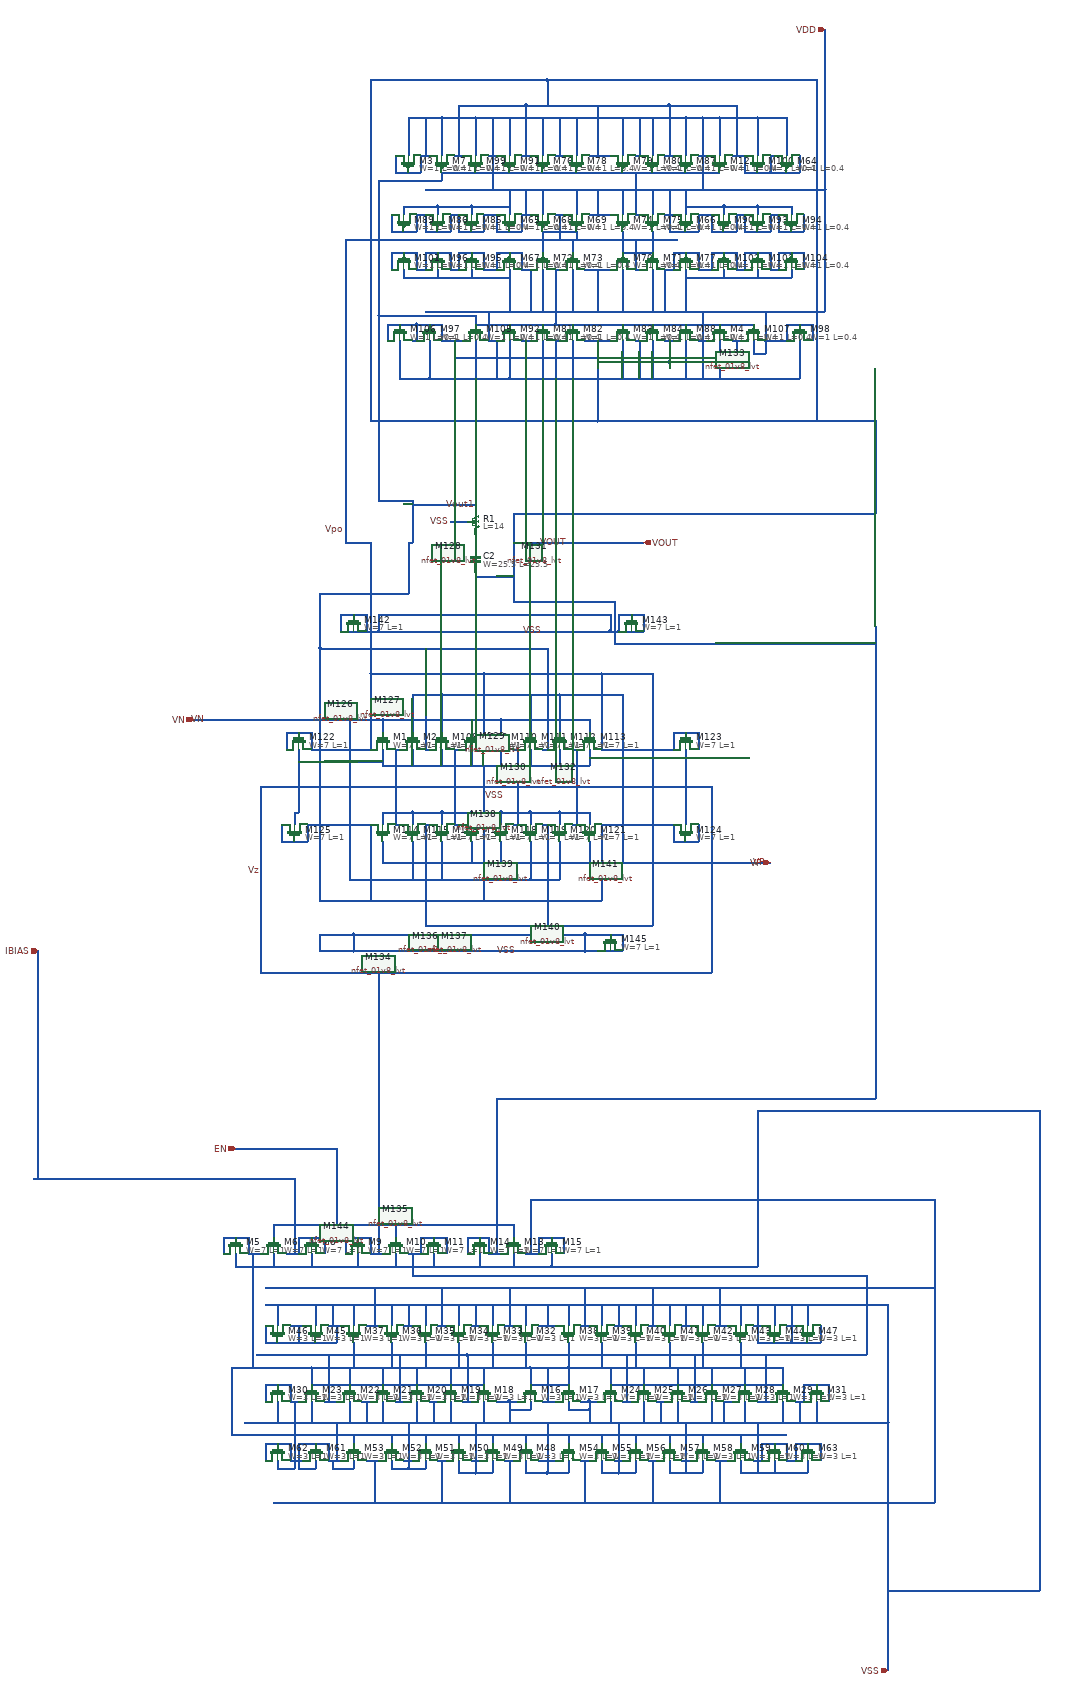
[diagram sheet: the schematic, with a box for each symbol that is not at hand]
v {xschem version=3.4.8RC file_version=1.2}
G {}
K {}
V {}
S {}
F {}
E {}
N 360 -1340 360 -1280 {lab=Vpo}
N 520 -1340 520 -1280 {lab=Vout1}
N 0 -860 40 -860 {lab=VN}
N 360 -1380 360 -1340 {lab=Vpo}
N 520 -1380 520 -1340 {lab=Vout1}
N -370 -310 -370 -70 {lab=IBIAS}
N 760 -1320 760 -1240 {lab=VOUT}
N 520 -1370 670 -1370 {lab=Vout1}
N 990 -1280 1070 -1280 {lab=VOUT}
N 890 -1280 990 -1280 {lab=VOUT}
N 760 -1280 890 -1280 {lab=VOUT}
N -370 -70 -370 -30 {lab=IBIAS}
N 760 -1340 760 -1320 {lab=VOUT}
N 760 -1240 760 -1190 {lab=VOUT}
N 670 -1290 670 -1270 {lab=#net1}
N 670 -1210 670 -1200 {lab=VOUT}
N 670 -1200 760 -1200 {lab=VOUT}
N 670 -1370 670 -1360 {lab=Vout1}
N 670 -1300 670 -1290 {lab=#net1}
N 1340 -520 1360 -520 {lab=VP}
N 1360 -520 1370 -520 {lab=VP}
N 610 -1330 650 -1330 {lab=VSS}
N 70 370 70 410 {lab=#net2}
N 70 370 100 370 {lab=#net2}
N 100 370 130 370 {lab=#net2}
N 130 370 130 410 {lab=#net2}
N 130 410 160 410 {lab=#net2}
N 220 410 250 410 {lab=IBIAS}
N 250 370 250 410 {lab=IBIAS}
N 250 370 280 370 {lab=IBIAS}
N 280 370 310 370 {lab=IBIAS}
N 310 370 310 410 {lab=IBIAS}
N 360 370 360 410 {lab=Vz}
N 360 370 390 370 {lab=Vz}
N 390 370 420 370 {lab=Vz}
N 420 370 420 410 {lab=Vz}
N 420 410 450 410 {lab=Vz}
N 510 410 540 410 {lab=#net3}
N 540 370 540 410 {lab=#net3}
N 540 370 570 370 {lab=#net3}
N 570 370 600 370 {lab=#net3}
N 600 370 600 410 {lab=#net3}
N 670 370 700 370 {lab=VOUT}
N 700 370 700 410 {lab=VOUT}
N 700 410 730 410 {lab=VOUT}
N 790 410 820 410 {lab=#net4}
N 820 370 820 410 {lab=#net4}
N 820 370 850 370 {lab=#net4}
N 850 370 880 370 {lab=#net4}
N 880 370 880 410 {lab=#net4}
N 190 340 570 340 {lab=EN}
N 570 340 760 340 {lab=EN}
N 760 340 760 370 {lab=EN}
N 480 340 480 370 {lab=EN}
N 830 760 860 760 {lab=#net2}
N 100 160 190 160 {lab=EN}
N 800 680 880 680 {lab=#net2}
N 890 680 890 720 {lab=#net2}
N 880 680 890 680 {lab=#net2}
N 800 680 800 720 {lab=#net2}
N 840 680 840 760 {lab=#net2}
N 800 720 840 720 {lab=#net2}
N 840 720 890 720 {lab=#net2}
N 750 760 770 760 {lab=VSS}
N 920 760 940 760 {lab=VSS}
N 720 760 750 760 {lab=VSS}
N 640 760 660 760 {lab=#net3}
N 560 760 580 760 {lab=VSS}
N 480 760 500 760 {lab=#net3}
N 400 760 420 760 {lab=VSS}
N 310 760 340 760 {lab=#net3}
N 280 680 800 680 {lab=#net2}
N 690 680 690 720 {lab=#net2}
N 610 680 610 720 {lab=#net2}
N 530 680 530 720 {lab=#net2}
N 450 680 450 720 {lab=#net2}
N 370 680 370 720 {lab=#net2}
N 280 680 280 720 {lab=#net2}
N 280 720 690 720 {lab=#net2}
N 650 650 650 760 {lab=#net3}
N 590 650 650 650 {lab=#net3}
N 940 760 960 760 {lab=VSS}
N 1020 760 1040 760 {lab=#net3}
N 1100 760 1120 760 {lab=VSS}
N 1180 760 1200 760 {lab=#net3}
N 1260 760 1280 760 {lab=VSS}
N 1340 760 1370 760 {lab=#net3}
N 650 650 1420 650 {lab=#net3}
N 150 650 590 650 {lab=#net3}
N 1030 650 1030 760 {lab=#net3}
N 800 280 800 410 {lab=#net4}
N 800 280 1170 280 {lab=#net4}
N 320 650 320 760 {lab=#net3}
N 1360 650 1360 760 {lab=#net3}
N 890 680 1400 680 {lab=#net2}
N 1400 680 1400 720 {lab=#net2}
N 1310 680 1310 720 {lab=#net2}
N 1230 680 1230 720 {lab=#net2}
N 1150 680 1150 720 {lab=#net2}
N 1070 680 1070 720 {lab=#net2}
N 990 690 990 720 {lab=#net2}
N 990 680 990 690 {lab=#net2}
N 990 720 1400 720 {lab=#net2}
N 490 650 490 760 {lab=#net3}
N 1190 650 1190 760 {lab=#net3}
N 230 760 250 760 {lab=VSS}
N 230 720 230 760 {lab=VSS}
N 200 720 230 720 {lab=VSS}
N 170 720 200 720 {lab=VSS}
N 170 720 170 760 {lab=VSS}
N 1430 760 1450 760 {lab=VSS}
N 1450 720 1450 760 {lab=VSS}
N 1450 720 1480 720 {lab=VSS}
N 1480 720 1510 720 {lab=VSS}
N 1510 720 1510 760 {lab=VSS}
N 90 680 280 680 {lab=#net2}
N 90 680 90 840 {lab=#net2}
N 90 840 1410 840 {lab=#net2}
N 190 340 190 370 {lab=EN}
N 440 60 440 410 {lab=Vz}
N 720 40 720 410 {lab=VOUT}
N 340 160 340 340 {lab=EN}
N 190 160 340 160 {lab=EN}
N -380 230 240 230 {lab=IBIAS}
N 240 230 240 410 {lab=IBIAS}
N 140 410 140 680 {lab=#net2}
N 380 620 380 680 {lab=#net2}
N 470 620 470 680 {lab=#net2}
N 550 620 550 680 {lab=#net2}
N 630 620 630 680 {lab=#net2}
N 710 620 710 680 {lab=#net2}
N 790 620 790 680 {lab=#net2}
N 890 620 890 680 {lab=#net2}
N 970 620 970 680 {lab=#net2}
N 1050 620 1050 680 {lab=#net2}
N 1130 620 1130 680 {lab=#net2}
N 1210 620 1210 680 {lab=#net2}
N 1300 620 1300 680 {lab=#net2}
N 380 840 380 860 {lab=#net2}
N 470 840 470 860 {lab=#net2}
N 550 840 550 860 {lab=#net2}
N 630 840 630 860 {lab=#net2}
N 710 840 710 860 {lab=#net2}
N 790 840 790 860 {lab=#net2}
N 890 840 890 860 {lab=#net2}
N 970 840 970 860 {lab=#net2}
N 1050 840 1050 860 {lab=#net2}
N 1130 840 1130 860 {lab=#net2}
N 1210 840 1210 860 {lab=#net2}
N 1300 840 1300 860 {lab=#net2}
N 230 580 260 580 {lab=VSS}
N 320 580 350 580 {lab=VSS}
N 410 580 440 580 {lab=#net4}
N 500 580 520 580 {lab=VSS}
N 580 580 600 580 {lab=#net4}
N 660 580 680 580 {lab=VSS}
N 740 580 760 580 {lab=#net4}
N 820 580 860 580 {lab=VSS}
N 920 580 940 580 {lab=#net4}
N 1000 580 1020 580 {lab=VSS}
N 1080 580 1100 580 {lab=#net4}
N 1160 580 1180 580 {lab=VSS}
N 1240 580 1270 580 {lab=#net4}
N 1330 580 1350 580 {lab=VSS}
N 1410 580 1430 580 {lab=VSS}
N 1340 580 1340 620 {lab=VSS}
N 1340 620 1380 620 {lab=VSS}
N 1380 620 1420 620 {lab=VSS}
N 1420 580 1420 620 {lab=VSS}
N 1420 620 1460 620 {lab=VSS}
N 1460 620 1490 620 {lab=VSS}
N 1490 580 1490 620 {lab=VSS}
N 1410 900 1430 900 {lab=VSS}
N 1430 860 1430 900 {lab=VSS}
N 1430 860 1460 860 {lab=VSS}
N 1460 860 1490 860 {lab=VSS}
N 1490 860 1490 900 {lab=VSS}
N 1410 860 1410 900 {lab=VSS}
N 1380 860 1410 860 {lab=VSS}
N 1350 860 1380 860 {lab=VSS}
N 1350 860 1350 900 {lab=VSS}
N 1330 900 1350 900 {lab=VSS}
N 1240 900 1270 900 {lab=#net4}
N 1160 900 1180 900 {lab=VSS}
N 1080 900 1100 900 {lab=#net4}
N 1000 900 1020 900 {lab=VSS}
N 920 900 940 900 {lab=#net4}
N 820 900 860 900 {lab=VSS}
N 740 900 760 900 {lab=#net4}
N 660 900 680 900 {lab=VSS}
N 580 900 600 900 {lab=#net4}
N 500 900 520 900 {lab=VSS}
N 410 900 440 900 {lab=#net4}
N 320 900 350 900 {lab=VSS}
N 230 900 260 900 {lab=VSS}
N 320 860 320 900 {lab=VSS}
N 290 860 320 860 {lab=VSS}
N 250 860 290 860 {lab=VSS}
N 250 860 250 900 {lab=VSS}
N 230 860 230 900 {lab=VSS}
N 200 860 230 860 {lab=VSS}
N 170 860 200 860 {lab=VSS}
N 170 860 170 900 {lab=VSS}
N 120 810 1650 810 {lab=VSS}
N 240 760 240 810 {lab=VSS}
N 240 810 240 900 {lab=VSS}
N 200 760 200 810 {lab=VSS}
N 280 760 280 810 {lab=VSS}
N 370 760 370 810 {lab=VSS}
N 410 760 410 810 {lab=VSS}
N 450 760 450 810 {lab=VSS}
N 170 580 170 620 {lab=VSS}
N 170 620 200 620 {lab=VSS}
N 200 620 250 620 {lab=VSS}
N 250 580 250 620 {lab=VSS}
N 240 620 290 620 {lab=VSS}
N 290 620 340 620 {lab=VSS}
N 340 580 340 620 {lab=VSS}
N 200 900 200 920 {lab=VSS}
N 200 920 240 920 {lab=VSS}
N 240 900 240 920 {lab=VSS}
N 290 900 290 920 {lab=VSS}
N 250 920 290 920 {lab=VSS}
N 250 900 250 920 {lab=VSS}
N 380 900 380 920 {lab=VSS}
N 330 920 380 920 {lab=VSS}
N 330 900 330 920 {lab=VSS}
N 340 810 340 900 {lab=VSS}
N 470 900 470 920 {lab=VSS}
N 470 920 510 920 {lab=VSS}
N 510 900 510 920 {lab=VSS}
N 510 810 510 900 {lab=VSS}
N 570 760 570 810 {lab=VSS}
N 530 760 530 810 {lab=VSS}
N 550 900 550 920 {lab=VSS}
N 510 920 550 920 {lab=VSS}
N 670 810 670 900 {lab=VSS}
N 610 760 610 810 {lab=VSS}
N 670 900 670 930 {lab=VSS}
N 630 930 670 930 {lab=VSS}
N 630 900 630 930 {lab=VSS}
N 670 930 710 930 {lab=VSS}
N 710 900 710 930 {lab=VSS}
N 690 760 690 810 {lab=VSS}
N 750 760 750 810 {lab=VSS}
N 800 760 800 780 {lab=VSS}
N 750 780 800 780 {lab=VSS}
N 840 810 840 900 {lab=VSS}
N 790 900 790 930 {lab=VSS}
N 790 930 840 930 {lab=VSS}
N 840 900 840 930 {lab=VSS}
N 840 930 890 930 {lab=VSS}
N 890 900 890 930 {lab=VSS}
N 890 760 890 780 {lab=VSS}
N 890 780 940 780 {lab=VSS}
N 940 760 940 780 {lab=VSS}
N 940 780 940 810 {lab=VSS}
N 1010 810 1010 900 {lab=VSS}
N 970 900 970 930 {lab=VSS}
N 970 930 1010 930 {lab=VSS}
N 1010 900 1010 930 {lab=VSS}
N 1050 900 1050 930 {lab=VSS}
N 1010 930 1050 930 {lab=VSS}
N 990 760 990 810 {lab=VSS}
N 1110 760 1110 810 {lab=VSS}
N 1070 760 1070 810 {lab=VSS}
N 1170 810 1170 900 {lab=VSS}
N 1130 900 1130 930 {lab=VSS}
N 1130 930 1210 930 {lab=VSS}
N 1210 900 1210 930 {lab=VSS}
N 1170 900 1170 930 {lab=VSS}
N 1150 760 1150 810 {lab=VSS}
N 1230 760 1230 810 {lab=VSS}
N 1310 760 1310 810 {lab=VSS}
N 1400 760 1400 810 {lab=VSS}
N 1440 760 1440 810 {lab=VSS}
N 1260 760 1260 810 {lab=VSS}
N 1340 810 1340 900 {lab=VSS}
N 1300 900 1300 930 {lab=VSS}
N 1300 930 1460 930 {lab=VSS}
N 1460 900 1460 930 {lab=VSS}
N 1380 900 1380 930 {lab=VSS}
N 170 530 1580 530 {lab=VSS}
N 1650 530 1650 810 {lab=VSS}
N 1580 530 1650 530 {lab=VSS}
N 1650 810 1650 1340 {lab=VSS}
N 200 530 200 580 {lab=VSS}
N 330 530 330 580 {lab=VSS}
N 290 530 290 580 {lab=VSS}
N 380 530 380 580 {lab=VSS}
N 510 530 510 580 {lab=VSS}
N 470 530 470 580 {lab=VSS}
N 550 530 550 580 {lab=VSS}
N 630 530 630 580 {lab=VSS}
N 670 530 670 580 {lab=VSS}
N 710 530 710 580 {lab=VSS}
N 790 530 790 580 {lab=VSS}
N 840 530 840 580 {lab=VSS}
N 890 530 890 580 {lab=VSS}
N 970 530 970 580 {lab=VSS}
N 1010 530 1010 580 {lab=VSS}
N 1050 530 1050 580 {lab=VSS}
N 1130 530 1130 580 {lab=VSS}
N 1170 530 1170 580 {lab=VSS}
N 1210 530 1210 580 {lab=VSS}
N 1300 530 1300 580 {lab=VSS}
N 1340 530 1340 580 {lab=VSS}
N 1380 530 1380 580 {lab=VSS}
N 1420 530 1420 580 {lab=VSS}
N 1460 530 1460 580 {lab=VSS}
N 1420 650 1580 650 {lab=#net3}
N 520 460 1580 460 {lab=#net3}
N 520 410 520 460 {lab=#net3}
N 190 1000 1760 1000 {lab=#net4}
N 1760 280 1760 1000 {lab=#net4}
N 1170 280 1760 280 {lab=#net4}
N 170 490 1760 490 {lab=#net4}
N 430 490 430 580 {lab=#net4}
N 590 490 590 580 {lab=#net4}
N 750 490 750 580 {lab=#net4}
N 930 490 930 580 {lab=#net4}
N 1090 490 1090 580 {lab=#net4}
N 1250 490 1250 580 {lab=#net4}
N 430 900 430 1000 {lab=#net4}
N 590 900 590 1000 {lab=#net4}
N 750 900 750 1000 {lab=#net4}
N 930 900 930 1000 {lab=#net4}
N 1090 900 1090 1000 {lab=#net4}
N 1250 900 1250 1000 {lab=#net4}
N 760 -1190 760 -1160 {lab=VOUT}
N 720 40 760 40 {lab=VOUT}
N -370 -30 -370 230 {lab=IBIAS}
N 2010 70 2010 1210 {lab=VSS}
N 1650 1210 2010 1210 {lab=VSS}
N 100 410 100 440 {lab=VSS}
N 100 440 190 440 {lab=VSS}
N 190 410 190 440 {lab=VSS}
N 190 440 280 440 {lab=VSS}
N 280 410 280 440 {lab=VSS}
N 280 440 390 440 {lab=VSS}
N 390 410 390 440 {lab=VSS}
N 390 440 480 440 {lab=VSS}
N 480 410 480 440 {lab=VSS}
N 480 440 570 440 {lab=VSS}
N 570 410 570 440 {lab=VSS}
N 570 440 680 440 {lab=VSS}
N 680 410 680 440 {lab=VSS}
N 680 440 760 440 {lab=VSS}
N 760 410 760 440 {lab=VSS}
N 760 440 850 440 {lab=VSS}
N 850 410 850 440 {lab=VSS}
N 850 440 1340 440 {lab=VSS}
N 1340 70 1340 440 {lab=VSS}
N 1340 900 1340 930 {lab=VSS}
N 1480 760 1480 810 {lab=VSS}
N 1580 650 1600 650 {lab=#net3}
N 1600 460 1600 650 {lab=#net3}
N 1580 460 1600 460 {lab=#net3}
N 650 370 650 410 {lab=VOUT}
N 650 370 670 370 {lab=VOUT}
N 860 -2060 880 -2060 {lab=Vpo}
N 1050 -1930 1060 -1930 {lab=Vpo}
N 780 -2000 1150 -2000 {lab=Vpo}
N 1020 -2000 1020 -1980 {lab=Vpo}
N 830 -2020 830 -2000 {lab=Vpo}
N 830 -2000 830 -1970 {lab=Vpo}
N 900 -2000 900 -1970 {lab=Vpo}
N 550 -2120 1500 -2120 {lab=VDD}
N 550 -1830 1500 -1830 {lab=VDD}
N 1500 -2120 1500 -1830 {lab=VDD}
N 1500 -2500 1500 -2120 {lab=VDD}
N 1020 -2020 1020 -2000 {lab=Vpo}
N 1090 -2020 1090 -2000 {lab=Vpo}
N 1090 -2000 1090 -1980 {lab=Vpo}
N 1050 -2060 1060 -2060 {lab=Vout1}
N 860 -1930 870 -1930 {lab=Vout1}
N 940 -2060 990 -2060 {lab=VDD}
N 960 -2120 960 -2060 {lab=VDD}
N 870 -2060 870 -2020 {lab=Vpo}
N 870 -2020 910 -2020 {lab=Vpo}
N 830 -2020 870 -2020 {lab=Vpo}
N 1020 -2120 1020 -2060 {lab=VDD}
N 1090 -2120 1090 -2060 {lab=VDD}
N 1020 -1980 1020 -1970 {lab=Vpo}
N 1090 -1980 1090 -1970 {lab=Vpo}
N 830 -1930 830 -1830 {lab=VDD}
N 900 -1930 900 -1830 {lab=VDD}
N 1020 -1930 1020 -1830 {lab=VDD}
N 1090 -1930 1090 -1830 {lab=VDD}
N 930 -1930 980 -1930 {lab=VDD}
N 980 -1930 990 -1930 {lab=VDD}
N 960 -1930 960 -1830 {lab=VDD}
N 1020 -1970 1090 -1970 {lab=Vpo}
N 910 -2020 910 -2000 {lab=Vpo}
N 360 -1870 360 -1540 {lab=Vpo}
N 1050 -2160 1050 -2060 {lab=Vout1}
N 750 -2160 830 -2160 {lab=Vout1}
N 830 -2160 910 -2160 {lab=Vout1}
N 910 -2160 1020 -2160 {lab=Vout1}
N 1020 -2160 1090 -2160 {lab=Vout1}
N 1090 -2160 1170 -2160 {lab=Vout1}
N 860 -1930 860 -1800 {lab=Vout1}
N 750 -1800 830 -1800 {lab=Vout1}
N 830 -1800 860 -1800 {lab=Vout1}
N 860 -1800 900 -1800 {lab=Vout1}
N 900 -1800 1020 -1800 {lab=Vout1}
N 1020 -1800 1090 -1800 {lab=Vout1}
N 1090 -1800 1170 -1800 {lab=Vout1}
N 750 -1760 750 -1670 {lab=VDD}
N 750 -1670 1170 -1670 {lab=VDD}
N 1170 -1760 1170 -1670 {lab=VDD}
N 1090 -1760 1090 -1670 {lab=VDD}
N 1020 -1760 1020 -1670 {lab=VDD}
N 900 -1760 900 -1670 {lab=VDD}
N 830 -1760 830 -1670 {lab=VDD}
N 590 -1760 630 -1760 {lab=VOUT}
N 590 -1800 590 -1760 {lab=VOUT}
N 560 -1800 590 -1800 {lab=VOUT}
N 530 -1800 560 -1800 {lab=VOUT}
N 530 -1800 530 -1760 {lab=VOUT}
N 700 -1830 700 -1760 {lab=VDD}
N 720 -1760 720 -1670 {lab=VDD}
N 720 -1670 750 -1670 {lab=VDD}
N 1390 -1760 1410 -1760 {lab=VDD}
N 1210 -1760 1210 -1670 {lab=VDD}
N 1170 -1670 1210 -1670 {lab=VDD}
N 1410 -1800 1410 -1760 {lab=VDD}
N 1410 -1800 1440 -1800 {lab=VDD}
N 1440 -1800 1470 -1800 {lab=VDD}
N 1470 -1800 1470 -1760 {lab=VDD}
N 1210 -1830 1210 -1760 {lab=VDD}
N 930 -1760 990 -1760 {lab=VOUT}
N 960 -1760 960 -1570 {lab=VOUT}
N 960 -1570 1620 -1570 {lab=VOUT}
N 780 -1760 800 -1760 {lab=VOUT}
N 1050 -1760 1060 -1760 {lab=VDD}
N 1120 -1760 1140 -1760 {lab=VOUT}
N 1060 -1760 1060 -1670 {lab=VDD}
N 860 -1760 870 -1760 {lab=VDD}
N 860 -1760 860 -1670 {lab=VDD}
N 790 -1760 790 -1720 {lab=VOUT}
N 790 -1720 960 -1720 {lab=VOUT}
N 1130 -1760 1130 -1710 {lab=VOUT}
N 960 -1710 1130 -1710 {lab=VOUT}
N 1440 -1760 1440 -1670 {lab=VDD}
N 1400 -1670 1440 -1670 {lab=VDD}
N 560 -1760 560 -1670 {lab=VDD}
N 560 -1670 630 -1670 {lab=VDD}
N 1280 -2200 1310 -2200 {lab=VOUT}
N 1310 -2200 1310 -2160 {lab=VOUT}
N 1310 -2160 1340 -2160 {lab=VOUT}
N 1340 -2160 1370 -2160 {lab=VOUT}
N 1370 -2200 1370 -2160 {lab=VOUT}
N 700 -2200 720 -2200 {lab=VDD}
N 710 -2200 710 -2120 {lab=VDD}
N 670 -2160 700 -2160 {lab=Vout1}
N 670 -2290 670 -2200 {lab=VDD}
N 670 -2290 1170 -2290 {lab=VDD}
N 1170 -2290 1170 -2200 {lab=VDD}
N 1210 -2290 1210 -2200 {lab=VDD}
N 1170 -2290 1210 -2290 {lab=VDD}
N 1210 -2200 1210 -2120 {lab=VDD}
N 1340 -2290 1340 -2200 {lab=VDD}
N 1120 -2200 1140 -2200 {lab=VOUT}
N 1050 -2200 1060 -2200 {lab=VDD}
N 1060 -2290 1060 -2200 {lab=VDD}
N 940 -2200 990 -2200 {lab=VOUT}
N 860 -2200 880 -2200 {lab=VDD}
N 870 -2290 870 -2200 {lab=VDD}
N 830 -2290 830 -2200 {lab=VDD}
N 910 -2290 910 -2200 {lab=VDD}
N 1020 -2290 1020 -2200 {lab=VDD}
N 1090 -2290 1090 -2200 {lab=VDD}
N 750 -2290 750 -2200 {lab=VDD}
N 710 -2290 710 -2200 {lab=VDD}
N 780 -2200 800 -2200 {lab=VOUT}
N 790 -2320 790 -2200 {lab=VOUT}
N 790 -2320 1130 -2320 {lab=VOUT}
N 1130 -2320 1130 -2200 {lab=VOUT}
N 960 -2320 960 -2200 {lab=VOUT}
N 840 -2380 840 -2320 {lab=VOUT}
N 490 -2380 840 -2380 {lab=VOUT}
N 490 -1570 960 -1570 {lab=VOUT}
N 840 -2380 1450 -2380 {lab=VOUT}
N 730 -2160 750 -2160 {lab=Vout1}
N 1170 -2160 1190 -2160 {lab=Vout1}
N 1170 -1800 1190 -1800 {lab=Vout1}
N 360 -1540 360 -1430 {lab=Vpo}
N 1050 -1970 1050 -1930 {lab=Vpo}
N 800 -1930 800 -1830 {lab=VDD}
N 700 -2160 730 -2160 {lab=Vout1}
N 620 -2200 640 -2200 {lab=VOUT}
N 590 -2160 670 -2160 {lab=Vout1}
N 590 -2290 590 -2200 {lab=VDD}
N 590 -2290 670 -2290 {lab=VDD}
N 540 -2200 560 -2200 {lab=VDD}
N 540 -2200 540 -2160 {lab=VDD}
N 510 -2160 540 -2160 {lab=VDD}
N 480 -2160 510 -2160 {lab=VDD}
N 480 -2200 480 -2160 {lab=VDD}
N 510 -2290 510 -2200 {lab=VDD}
N 510 -2290 590 -2290 {lab=VDD}
N 550 -2290 550 -2200 {lab=VDD}
N 420 -2380 420 -1570 {lab=VOUT}
N 420 -1570 490 -1570 {lab=VOUT}
N 420 -2380 490 -2380 {lab=VOUT}
N 1200 -2200 1220 -2200 {lab=VDD}
N 1190 -2160 1250 -2160 {lab=Vout1}
N 1370 -2200 1380 -2200 {lab=VOUT}
N 1370 -2160 1410 -2160 {lab=VOUT}
N 1410 -2160 1440 -2160 {lab=VOUT}
N 1440 -2200 1440 -2160 {lab=VOUT}
N 1410 -2290 1410 -2200 {lab=VDD}
N 1340 -2290 1410 -2290 {lab=VDD}
N 360 -2000 780 -2000 {lab=Vpo}
N 360 -2000 360 -1870 {lab=Vpo}
N 1050 -2000 1050 -1970 {lab=Vpo}
N 870 -2020 870 -2000 {lab=Vpo}
N 830 -2120 830 -2060 {lab=VDD}
N 780 -2060 800 -2060 {lab=VDD}
N 780 -2060 780 -2020 {lab=VDD}
N 750 -2020 780 -2020 {lab=VDD}
N 720 -2020 750 -2020 {lab=VDD}
N 720 -2060 720 -2020 {lab=VDD}
N 1120 -2060 1140 -2060 {lab=VDD}
N 1130 -2060 1130 -2020 {lab=VDD}
N 1130 -2020 1170 -2020 {lab=VDD}
N 1170 -2020 1200 -2020 {lab=VDD}
N 1200 -2060 1200 -2020 {lab=VDD}
N 790 -2120 790 -2060 {lab=VDD}
N 1130 -2120 1130 -2060 {lab=VDD}
N 1170 -2120 1170 -2060 {lab=VDD}
N 750 -2120 750 -2060 {lab=VDD}
N 780 -1930 800 -1930 {lab=VDD}
N 780 -1970 780 -1930 {lab=VDD}
N 750 -1970 780 -1970 {lab=VDD}
N 720 -1970 750 -1970 {lab=VDD}
N 720 -1970 720 -1930 {lab=VDD}
N 750 -1930 750 -1830 {lab=VDD}
N 1120 -1930 1140 -1930 {lab=VDD}
N 1140 -1970 1140 -1930 {lab=VDD}
N 1140 -1970 1170 -1970 {lab=VDD}
N 1170 -1970 1200 -1970 {lab=VDD}
N 1200 -1970 1200 -1930 {lab=VDD}
N 1170 -1930 1170 -1840 {lab=VDD}
N 1170 -1840 1170 -1830 {lab=VDD}
N 690 -2060 720 -2060 {lab=VDD}
N 690 -2060 690 -2020 {lab=VDD}
N 660 -2020 690 -2020 {lab=VDD}
N 630 -2020 660 -2020 {lab=VDD}
N 630 -2060 630 -2020 {lab=VDD}
N 610 -2060 630 -2060 {lab=VDD}
N 610 -2060 610 -2020 {lab=VDD}
N 580 -2020 610 -2020 {lab=VDD}
N 550 -2020 580 -2020 {lab=VDD}
N 550 -2060 550 -2020 {lab=VDD}
N 530 -2060 550 -2060 {lab=VDD}
N 530 -2060 530 -2020 {lab=VDD}
N 500 -2020 530 -2020 {lab=VDD}
N 470 -2020 500 -2020 {lab=VDD}
N 470 -2060 470 -2020 {lab=VDD}
N 500 -2080 500 -2060 {lab=VDD}
N 500 -2080 580 -2080 {lab=VDD}
N 580 -2080 580 -2060 {lab=VDD}
N 580 -2080 660 -2080 {lab=VDD}
N 660 -2080 660 -2060 {lab=VDD}
N 660 -2080 750 -2080 {lab=VDD}
N 1200 -2060 1230 -2060 {lab=VDD}
N 1230 -2060 1230 -2020 {lab=VDD}
N 1230 -2020 1260 -2020 {lab=VDD}
N 1260 -2020 1290 -2020 {lab=VDD}
N 1290 -2060 1290 -2020 {lab=VDD}
N 1290 -2060 1310 -2060 {lab=VDD}
N 1310 -2060 1310 -2020 {lab=VDD}
N 1310 -2020 1340 -2020 {lab=VDD}
N 1340 -2020 1370 -2020 {lab=VDD}
N 1370 -2060 1370 -2020 {lab=VDD}
N 1370 -2060 1390 -2060 {lab=VDD}
N 1390 -2060 1390 -2020 {lab=VDD}
N 1390 -2020 1420 -2020 {lab=VDD}
N 1420 -2020 1450 -2020 {lab=VDD}
N 1450 -2060 1450 -2020 {lab=VDD}
N 1420 -2080 1420 -2060 {lab=VDD}
N 1340 -2080 1420 -2080 {lab=VDD}
N 1340 -2080 1340 -2060 {lab=VDD}
N 1260 -2080 1340 -2080 {lab=VDD}
N 1260 -2080 1260 -2060 {lab=VDD}
N 1170 -2080 1260 -2080 {lab=VDD}
N 1480 -2380 1480 -1570 {lab=VOUT}
N 1450 -2380 1480 -2380 {lab=VOUT}
N 690 -1930 720 -1930 {lab=VDD}
N 690 -1970 690 -1930 {lab=VDD}
N 660 -1970 690 -1970 {lab=VDD}
N 630 -1970 660 -1970 {lab=VDD}
N 630 -1970 630 -1930 {lab=VDD}
N 610 -1930 630 -1930 {lab=VDD}
N 610 -1970 610 -1930 {lab=VDD}
N 580 -1970 610 -1970 {lab=VDD}
N 550 -1970 580 -1970 {lab=VDD}
N 550 -1970 550 -1930 {lab=VDD}
N 530 -1930 550 -1930 {lab=VDD}
N 530 -1970 530 -1930 {lab=VDD}
N 500 -1970 530 -1970 {lab=VDD}
N 470 -1970 500 -1970 {lab=VDD}
N 470 -1970 470 -1930 {lab=VDD}
N 500 -1930 500 -1910 {lab=VDD}
N 500 -1910 580 -1910 {lab=VDD}
N 580 -1930 580 -1910 {lab=VDD}
N 580 -1910 660 -1910 {lab=VDD}
N 660 -1930 660 -1910 {lab=VDD}
N 660 -1910 750 -1910 {lab=VDD}
N 1230 -1970 1230 -1930 {lab=VDD}
N 1230 -1970 1260 -1970 {lab=VDD}
N 1260 -1970 1290 -1970 {lab=VDD}
N 1290 -1970 1290 -1930 {lab=VDD}
N 1290 -1930 1310 -1930 {lab=VDD}
N 1310 -1970 1310 -1930 {lab=VDD}
N 1310 -1970 1340 -1970 {lab=VDD}
N 1340 -1970 1370 -1970 {lab=VDD}
N 1370 -1970 1370 -1930 {lab=VDD}
N 1370 -1930 1390 -1930 {lab=VDD}
N 1390 -1970 1390 -1930 {lab=VDD}
N 1390 -1970 1420 -1970 {lab=VDD}
N 1420 -1970 1450 -1970 {lab=VDD}
N 1450 -1970 1450 -1930 {lab=VDD}
N 1420 -1930 1420 -1910 {lab=VDD}
N 1340 -1910 1420 -1910 {lab=VDD}
N 1340 -1930 1340 -1910 {lab=VDD}
N 1260 -1910 1340 -1910 {lab=VDD}
N 1260 -1930 1260 -1910 {lab=VDD}
N 1170 -1910 1260 -1910 {lab=VDD}
N 1200 -1930 1230 -1930 {lab=VDD}
N 700 -1760 720 -1760 {lab=VDD}
N 630 -1760 640 -1760 {lab=VOUT}
N 630 -1670 720 -1670 {lab=VDD}
N 490 -1800 530 -1800 {lab=VOUT}
N 520 -1760 530 -1760 {lab=VOUT}
N 460 -1800 460 -1760 {lab=VOUT}
N 460 -1800 490 -1800 {lab=VOUT}
N 490 -1760 490 -1670 {lab=VDD}
N 490 -1670 560 -1670 {lab=VDD}
N 630 -2320 630 -2200 {lab=VOUT}
N 630 -2320 790 -2320 {lab=VOUT}
N 1130 -2320 1290 -2320 {lab=VOUT}
N 620 -1760 620 -1720 {lab=VOUT}
N 620 -1720 790 -1720 {lab=VOUT}
N 1200 -1760 1220 -1760 {lab=VDD}
N 1250 -1760 1250 -1670 {lab=VDD}
N 1210 -1670 1250 -1670 {lab=VDD}
N 1190 -1800 1250 -1800 {lab=Vout1}
N 670 -1800 750 -1800 {lab=Vout1}
N 1280 -1760 1300 -1760 {lab=VOUT}
N 1360 -1830 1360 -1760 {lab=VDD}
N 1330 -1760 1330 -1730 {lab=VDD}
N 1330 -1730 1360 -1730 {lab=VDD}
N 1360 -1760 1360 -1730 {lab=VDD}
N 1360 -1760 1390 -1760 {lab=VDD}
N 1250 -1670 1400 -1670 {lab=VDD}
N 1290 -1760 1290 -1710 {lab=VOUT}
N 1130 -1710 1290 -1710 {lab=VOUT}
N 1250 -1800 1330 -1800 {lab=Vout1}
N 360 -1430 360 -1380 {lab=Vpo}
N 590 -2160 590 -2140 {lab=Vout1}
N 670 -1820 670 -1800 {lab=Vout1}
N 440 -1820 670 -1820 {lab=Vout1}
N 440 -2140 440 -1820 {lab=Vout1}
N 440 -2140 590 -2140 {lab=Vout1}
N 440 -1820 440 -1380 {lab=Vout1}
N 440 -1380 520 -1380 {lab=Vout1}
N 1620 -1570 1620 -1350 {lab=VOUT}
N 760 -1350 1620 -1350 {lab=VOUT}
N 760 -1350 760 -1340 {lab=VOUT}
N 1290 -2320 1290 -2200 {lab=VOUT}
N 1250 -2290 1250 -2200 {lab=VDD}
N 1210 -2290 1250 -2290 {lab=VDD}
N 1250 -2290 1340 -2290 {lab=VDD}
N 670 -1760 670 -1670 {lab=VDD}
N 910 -2120 910 -2060 {lab=VDD}
N 1120 -1930 1120 -1830 {lab=VDD}
N 450 -860 450 -830 {lab=VN}
N 450 -860 730 -860 {lab=VN}
N 730 -860 730 -830 {lab=VN}
N 660 -860 660 -830 {lab=VN}
N 660 -570 660 -520 {lab=VP}
N 660 -520 950 -520 {lab=VP}
N 730 -570 730 -520 {lab=VP}
N 730 -860 940 -860 {lab=VN}
N 940 -860 940 -830 {lab=VN}
N 450 -570 450 -520 {lab=VP}
N 450 -520 660 -520 {lab=VP}
N 940 -570 940 -520 {lab=VP}
N 270 -860 450 -860 {lab=VN}
N 950 -520 1150 -520 {lab=VP}
N 480 -790 490 -790 {lab=Vz}
N 550 -790 560 -790 {lab=Vout1}
N 620 -790 630 -790 {lab=Vz}
N 690 -790 700 -790 {lab=Vpo}
N 760 -790 770 -790 {lab=Vz}
N 830 -790 840 -790 {lab=Vout1}
N 900 -790 910 -790 {lab=Vz}
N 480 -610 490 -610 {lab=Vz}
N 620 -610 630 -610 {lab=Vz}
N 690 -610 700 -610 {lab=Vout1}
N 760 -610 770 -610 {lab=Vz}
N 830 -610 840 -610 {lab=Vpo}
N 900 -610 910 -610 {lab=Vz}
N 370 -860 370 -480 {lab=VN}
N 370 -480 520 -480 {lab=VN}
N 520 -570 520 -480 {lab=VN}
N 590 -570 590 -480 {lab=VN}
N 520 -480 590 -480 {lab=VN}
N 590 -480 800 -480 {lab=VN}
N 800 -570 800 -480 {lab=VN}
N 800 -480 870 -480 {lab=VN}
N 870 -570 870 -480 {lab=VN}
N 1020 -920 1020 -540 {lab=VP}
N 870 -920 1020 -920 {lab=VP}
N 870 -920 870 -830 {lab=VP}
N 800 -920 800 -830 {lab=VP}
N 800 -920 870 -920 {lab=VP}
N 590 -920 800 -920 {lab=VP}
N 590 -920 590 -830 {lab=VP}
N 520 -920 590 -920 {lab=VP}
N 520 -920 520 -830 {lab=VP}
N 1020 -540 1020 -520 {lab=VP}
N 690 -970 690 -790 {lab=Vpo}
N 420 -970 420 -790 {lab=Vpo}
N 970 -970 970 -790 {lab=Vpo}
N 420 -970 690 -970 {lab=Vpo}
N 690 -970 970 -970 {lab=Vpo}
N 690 -610 690 -430 {lab=Vout1}
N 420 -610 420 -430 {lab=Vout1}
N 970 -610 970 -430 {lab=Vout1}
N 420 -430 690 -430 {lab=Vout1}
N 690 -430 970 -430 {lab=Vout1}
N 420 -1200 420 -970 {lab=Vpo}
N 550 -610 560 -610 {lab=Vpo}
N 550 -610 550 -370 {lab=Vpo}
N 840 -610 840 -370 {lab=Vpo}
N 550 -370 1090 -370 {lab=Vpo}
N 1090 -970 1090 -370 {lab=Vpo}
N 970 -970 1090 -970 {lab=Vpo}
N 840 -1030 840 -790 {lab=Vout1}
N 550 -1030 550 -790 {lab=Vout1}
N 300 -1030 840 -1030 {lab=Vout1}
N 300 -1030 300 -430 {lab=Vout1}
N 300 -430 420 -430 {lab=Vout1}
N 40 -860 270 -860 {lab=VN}
N 1150 -520 1340 -520 {lab=VP}
N 160 -700 1230 -700 {lab=Vz}
N 160 -700 160 -260 {lab=Vz}
N 160 -260 690 -260 {lab=Vz}
N 1230 -700 1230 -260 {lab=Vz}
N 690 -260 1230 -260 {lab=Vz}
N 300 -1160 300 -1030 {lab=Vout1}
N 300 -1160 510 -1160 {lab=Vout1}
N 510 -1200 510 -1160 {lab=Vout1}
N 480 -790 480 -700 {lab=Vz}
N 620 -790 620 -700 {lab=Vz}
N 770 -790 770 -700 {lab=Vz}
N 910 -790 910 -700 {lab=Vz}
N 480 -700 480 -610 {lab=Vz}
N 620 -700 620 -610 {lab=Vz}
N 770 -700 770 -620 {lab=Vz}
N 910 -700 910 -610 {lab=Vz}
N 450 -790 450 -750 {lab=VSS}
N 450 -750 940 -750 {lab=VSS}
N 940 -790 940 -750 {lab=VSS}
N 870 -790 870 -750 {lab=VSS}
N 800 -790 800 -750 {lab=VSS}
N 660 -790 660 -750 {lab=VSS}
N 590 -790 590 -750 {lab=VSS}
N 520 -790 520 -750 {lab=VSS}
N 450 -640 450 -610 {lab=VSS}
N 450 -640 520 -640 {lab=VSS}
N 520 -640 520 -610 {lab=VSS}
N 520 -640 590 -640 {lab=VSS}
N 590 -640 590 -610 {lab=VSS}
N 590 -640 660 -640 {lab=VSS}
N 660 -640 660 -610 {lab=VSS}
N 660 -640 730 -640 {lab=VSS}
N 730 -640 730 -610 {lab=VSS}
N 730 -640 800 -640 {lab=VSS}
N 800 -640 800 -610 {lab=VSS}
N 800 -640 870 -640 {lab=VSS}
N 870 -640 870 -610 {lab=VSS}
N 870 -640 940 -640 {lab=VSS}
N 940 -640 940 -610 {lab=VSS}
N 360 -1280 420 -1280 {lab=Vpo}
N 510 -1280 520 -1280 {lab=Vout1}
N 690 -680 690 -640 {lab=VSS}
N 690 -750 690 -680 {lab=VSS}
N 440 -260 440 60 {lab=Vz}
N 1340 70 1840 70 {lab=VSS}
N 1840 70 2010 70 {lab=VSS}
N 760 40 1220 40 {lab=VOUT}
N 1220 40 1390 40 {lab=VOUT}
N 1390 40 1620 40 {lab=VOUT}
N 1620 -1080 1620 40 {lab=VOUT}
N 770 -620 770 -610 {lab=Vz}
N 730 -790 730 -750 {lab=VSS}
N 280 -790 420 -790 {lab=Vpo}
N 250 -830 280 -830 {lab=Vpo}
N 280 -830 280 -790 {lab=Vpo}
N 220 -830 250 -830 {lab=Vpo}
N 220 -830 220 -790 {lab=Vpo}
N 970 -790 1140 -790 {lab=Vpo}
N 1140 -830 1140 -790 {lab=Vpo}
N 1140 -830 1170 -830 {lab=Vpo}
N 1170 -830 1200 -830 {lab=Vpo}
N 1200 -830 1200 -790 {lab=Vpo}
N 970 -610 1140 -610 {lab=Vout1}
N 1140 -610 1140 -570 {lab=Vout1}
N 1140 -570 1170 -570 {lab=Vout1}
N 1170 -570 1200 -570 {lab=Vout1}
N 1200 -610 1200 -570 {lab=Vout1}
N 270 -610 420 -610 {lab=Vout1}
N 270 -610 270 -570 {lab=Vout1}
N 240 -570 270 -570 {lab=Vout1}
N 210 -570 240 -570 {lab=Vout1}
N 210 -610 210 -570 {lab=Vout1}
N 250 -790 250 -640 {lab=VSS}
N 240 -640 250 -640 {lab=VSS}
N 240 -640 240 -610 {lab=VSS}
N 250 -760 450 -760 {lab=VSS}
N 1170 -790 1170 -610 {lab=VSS}
N 940 -770 1170 -770 {lab=VSS}
N 440 -1110 440 -1070 {lab=VSS}
N 440 -1110 990 -1110 {lab=VSS}
N 990 -1110 990 -1070 {lab=VSS}
N 440 -1070 990 -1070 {lab=VSS}
N 380 -350 380 -310 {lab=VSS}
N 380 -350 930 -350 {lab=VSS}
N 930 -350 930 -310 {lab=VSS}
N 380 -310 930 -310 {lab=VSS}
N 760 -1160 760 -1140 {lab=VOUT}
N 760 -1140 1000 -1140 {lab=VOUT}
N 1000 -1140 1000 -1040 {lab=VOUT}
N 1000 -1040 1620 -1040 {lab=VOUT}
N 410 -1070 440 -1070 {lab=VSS}
N 410 -1110 410 -1070 {lab=VSS}
N 380 -1110 410 -1110 {lab=VSS}
N 350 -1110 380 -1110 {lab=VSS}
N 350 -1110 350 -1070 {lab=VSS}
N 350 -1070 380 -1070 {lab=VSS}
N 380 -1070 410 -1070 {lab=VSS}
N 990 -1070 1010 -1070 {lab=VSS}
N 1010 -1110 1010 -1070 {lab=VSS}
N 1010 -1110 1040 -1110 {lab=VSS}
N 1040 -1110 1070 -1110 {lab=VSS}
N 1070 -1110 1070 -1070 {lab=VSS}
N 1010 -1070 1070 -1070 {lab=VSS}
N 930 -310 960 -310 {lab=VSS}
N 930 -350 990 -350 {lab=VSS}
N 990 -350 1020 -350 {lab=VSS}
N 1020 -350 1020 -310 {lab=VSS}
N 960 -310 1020 -310 {lab=VSS}
N 300 -310 380 -310 {lab=VSS}
N 300 -350 300 -310 {lab=VSS}
N 300 -350 380 -350 {lab=VSS}
N 420 -1280 420 -1260 {lab=Vpo}
N 510 -1220 510 -1200 {lab=Vout1}
N 420 -1260 420 -1200 {lab=Vpo}
N 510 -1280 510 -1220 {lab=Vout1}
N 1650 1340 1650 1400 {lab=VSS}
C {iopin.sym} 1650 1400 1 0 {name=p4 lab=VSS}
C {lab_wire.sym} 30 -860 0 0 {name=p7 sig_type=std_logic lab=VN}
C {lab_wire.sym} 360 -1310 0 0 {name=p8 sig_type=std_logic lab=Vpo}
C {lab_wire.sym} 1360 -520 0 0 {name=p9 sig_type=std_logic lab=VP}
C {devices/launcher.sym} 40 -100 0 0 {name=h15
descr="Annotate OP" 
tclcommand="set show_hidden_texts 1; xschem annotate_op"
}
C {lab_wire.sym} 670 -1370 0 0 {name=p10 sig_type=std_logic lab=Vout1}
C {lab_wire.sym} 160 -500 0 0 {name=p11 sig_type=std_logic lab=Vz}
C {iopin.sym} 1500 -2500 3 0 {name=p3 lab=VDD}
C {iopin.sym} -370 -310 3 0 {name=p6 lab=IBIAS}
C {opin.sym} 1070 -1280 0 0 {name=p13 lab=VOUT}
C {lab_wire.sym} 890 -1280 0 0 {name=p21 sig_type=std_logic lab=VOUT}
C {iopin.sym} 100 160 2 0 {name=p5 lab=EN}
C {iopin.sym} 0 -860 2 0 {name=p12 lab=VN}
C {iopin.sym} 1370 -520 0 0 {name=p1 lab=VP}
C {lab_wire.sym} 690 -680 2 0 {name=p18 sig_type=std_logic lab=VSS}
C {lab_wire.sym} 610 -1330 0 0 {name=p14 sig_type=std_logic lab=VSS}
C {sky130_fd_pr/cap_mim_m3_1.sym} 670 -1240 0 0 {name=C2 model=cap_mim_m3_1 W=25.5 L=25.5 MF=1 spiceprefix=X}
C {sky130_fd_pr/nfet_01v8_lvt.sym} 100 390 3 1 {name=M5
W=7
L=1
nf=1
mult=1
ad="expr('int((@nf + 1)/2) * @W / @nf * 0.29')"
pd="expr('2*int((@nf + 1)/2) * (@W / @nf + 0.29)')"
as="expr('int((@nf + 2)/2) * @W / @nf * 0.29')"
ps="expr('2*int((@nf + 2)/2) * (@W / @nf + 0.29)')"
nrd="expr('0.29 / @W ')" nrs="expr('0.29 / @W ')"
sa=0 sb=0 sd=0
model=nfet_01v8_lvt
spiceprefix=X
}
C {sky130_fd_pr/nfet_01v8_lvt.sym} 190 390 1 0 {name=M6
W=7
L=1
nf=1
mult=1
ad="expr('int((@nf + 1)/2) * @W / @nf * 0.29')"
pd="expr('2*int((@nf + 1)/2) * (@W / @nf + 0.29)')"
as="expr('int((@nf + 2)/2) * @W / @nf * 0.29')"
ps="expr('2*int((@nf + 2)/2) * (@W / @nf + 0.29)')"
nrd="expr('0.29 / @W ')" nrs="expr('0.29 / @W ')"
sa=0 sb=0 sd=0
model=nfet_01v8_lvt
spiceprefix=X
}
C {sky130_fd_pr/nfet_01v8_lvt.sym} 280 390 3 1 {name=M8
W=7
L=1
nf=1
mult=1
ad="expr('int((@nf + 1)/2) * @W / @nf * 0.29')"
pd="expr('2*int((@nf + 1)/2) * (@W / @nf + 0.29)')"
as="expr('int((@nf + 2)/2) * @W / @nf * 0.29')"
ps="expr('2*int((@nf + 2)/2) * (@W / @nf + 0.29)')"
nrd="expr('0.29 / @W ')" nrs="expr('0.29 / @W ')"
sa=0 sb=0 sd=0
model=nfet_01v8_lvt
spiceprefix=X
}
C {sky130_fd_pr/nfet_01v8_lvt.sym} 390 390 3 1 {name=M9
W=7
L=1
nf=1
mult=1
ad="expr('int((@nf + 1)/2) * @W / @nf * 0.29')"
pd="expr('2*int((@nf + 1)/2) * (@W / @nf + 0.29)')"
as="expr('int((@nf + 2)/2) * @W / @nf * 0.29')"
ps="expr('2*int((@nf + 2)/2) * (@W / @nf + 0.29)')"
nrd="expr('0.29 / @W ')" nrs="expr('0.29 / @W ')"
sa=0 sb=0 sd=0
model=nfet_01v8_lvt
spiceprefix=X
}
C {sky130_fd_pr/nfet_01v8_lvt.sym} 480 390 3 1 {name=M10
W=7
L=1
nf=1
mult=1
ad="expr('int((@nf + 1)/2) * @W / @nf * 0.29')"
pd="expr('2*int((@nf + 1)/2) * (@W / @nf + 0.29)')"
as="expr('int((@nf + 2)/2) * @W / @nf * 0.29')"
ps="expr('2*int((@nf + 2)/2) * (@W / @nf + 0.29)')"
nrd="expr('0.29 / @W ')" nrs="expr('0.29 / @W ')"
sa=0 sb=0 sd=0
model=nfet_01v8_lvt
spiceprefix=X
}
C {sky130_fd_pr/nfet_01v8_lvt.sym} 570 390 3 1 {name=M11
W=7
L=1
nf=1
mult=1
ad="expr('int((@nf + 1)/2) * @W / @nf * 0.29')"
pd="expr('2*int((@nf + 1)/2) * (@W / @nf + 0.29)')"
as="expr('int((@nf + 2)/2) * @W / @nf * 0.29')"
ps="expr('2*int((@nf + 2)/2) * (@W / @nf + 0.29)')"
nrd="expr('0.29 / @W ')" nrs="expr('0.29 / @W ')"
sa=0 sb=0 sd=0
model=nfet_01v8_lvt
spiceprefix=X
}
C {sky130_fd_pr/nfet_01v8_lvt.sym} 760 390 3 1 {name=M13
W=7
L=1
nf=1
mult=1
ad="expr('int((@nf + 1)/2) * @W / @nf * 0.29')"
pd="expr('2*int((@nf + 1)/2) * (@W / @nf + 0.29)')"
as="expr('int((@nf + 2)/2) * @W / @nf * 0.29')"
ps="expr('2*int((@nf + 2)/2) * (@W / @nf + 0.29)')"
nrd="expr('0.29 / @W ')" nrs="expr('0.29 / @W ')"
sa=0 sb=0 sd=0
model=nfet_01v8_lvt
spiceprefix=X
}
C {sky130_fd_pr/nfet_01v8_lvt.sym} 680 390 1 0 {name=M14
W=7
L=1
nf=1
mult=1
ad="expr('int((@nf + 1)/2) * @W / @nf * 0.29')"
pd="expr('2*int((@nf + 1)/2) * (@W / @nf + 0.29)')"
as="expr('int((@nf + 2)/2) * @W / @nf * 0.29')"
ps="expr('2*int((@nf + 2)/2) * (@W / @nf + 0.29)')"
nrd="expr('0.29 / @W ')" nrs="expr('0.29 / @W ')"
sa=0 sb=0 sd=0
model=nfet_01v8_lvt
spiceprefix=X
}
C {sky130_fd_pr/nfet_01v8_lvt.sym} 850 390 3 1 {name=M15
W=7
L=1
nf=1
mult=1
ad="expr('int((@nf + 1)/2) * @W / @nf * 0.29')"
pd="expr('2*int((@nf + 1)/2) * (@W / @nf + 0.29)')"
as="expr('int((@nf + 2)/2) * @W / @nf * 0.29')"
ps="expr('2*int((@nf + 2)/2) * (@W / @nf + 0.29)')"
nrd="expr('0.29 / @W ')" nrs="expr('0.29 / @W ')"
sa=0 sb=0 sd=0
model=nfet_01v8_lvt
spiceprefix=X
}
C {sky130_fd_pr/nfet_01v8_lvt.sym} 800 740 1 0 {name=M16
W=3
L=1
nf=1
mult=1
ad="expr('int((@nf + 1)/2) * @W / @nf * 0.29')"
pd="expr('2*int((@nf + 1)/2) * (@W / @nf + 0.29)')"
as="expr('int((@nf + 2)/2) * @W / @nf * 0.29')"
ps="expr('2*int((@nf + 2)/2) * (@W / @nf + 0.29)')"
nrd="expr('0.29 / @W ')" nrs="expr('0.29 / @W ')"
sa=0 sb=0 sd=0
model=nfet_01v8_lvt
spiceprefix=X
}
C {sky130_fd_pr/nfet_01v8_lvt.sym} 890 740 3 1 {name=M17
W=3
L=1
nf=1
mult=1
ad="expr('int((@nf + 1)/2) * @W / @nf * 0.29')"
pd="expr('2*int((@nf + 1)/2) * (@W / @nf + 0.29)')"
as="expr('int((@nf + 2)/2) * @W / @nf * 0.29')"
ps="expr('2*int((@nf + 2)/2) * (@W / @nf + 0.29)')"
nrd="expr('0.29 / @W ')" nrs="expr('0.29 / @W ')"
sa=0 sb=0 sd=0
model=nfet_01v8_lvt
spiceprefix=X
}
C {sky130_fd_pr/nfet_01v8_lvt.sym} 690 740 3 1 {name=M18
W=3
L=1
nf=1
mult=1
ad="expr('int((@nf + 1)/2) * @W / @nf * 0.29')"
pd="expr('2*int((@nf + 1)/2) * (@W / @nf + 0.29)')"
as="expr('int((@nf + 2)/2) * @W / @nf * 0.29')"
ps="expr('2*int((@nf + 2)/2) * (@W / @nf + 0.29)')"
nrd="expr('0.29 / @W ')" nrs="expr('0.29 / @W ')"
sa=0 sb=0 sd=0
model=nfet_01v8_lvt
spiceprefix=X
}
C {sky130_fd_pr/nfet_01v8_lvt.sym} 610 740 1 0 {name=M19
W=3
L=1
nf=1
mult=1
ad="expr('int((@nf + 1)/2) * @W / @nf * 0.29')"
pd="expr('2*int((@nf + 1)/2) * (@W / @nf + 0.29)')"
as="expr('int((@nf + 2)/2) * @W / @nf * 0.29')"
ps="expr('2*int((@nf + 2)/2) * (@W / @nf + 0.29)')"
nrd="expr('0.29 / @W ')" nrs="expr('0.29 / @W ')"
sa=0 sb=0 sd=0
model=nfet_01v8_lvt
spiceprefix=X
}
C {sky130_fd_pr/nfet_01v8_lvt.sym} 530 740 3 1 {name=M20
W=3
L=1
nf=1
mult=1
ad="expr('int((@nf + 1)/2) * @W / @nf * 0.29')"
pd="expr('2*int((@nf + 1)/2) * (@W / @nf + 0.29)')"
as="expr('int((@nf + 2)/2) * @W / @nf * 0.29')"
ps="expr('2*int((@nf + 2)/2) * (@W / @nf + 0.29)')"
nrd="expr('0.29 / @W ')" nrs="expr('0.29 / @W ')"
sa=0 sb=0 sd=0
model=nfet_01v8_lvt
spiceprefix=X
}
C {sky130_fd_pr/nfet_01v8_lvt.sym} 450 740 1 0 {name=M21
W=3
L=1
nf=1
mult=1
ad="expr('int((@nf + 1)/2) * @W / @nf * 0.29')"
pd="expr('2*int((@nf + 1)/2) * (@W / @nf + 0.29)')"
as="expr('int((@nf + 2)/2) * @W / @nf * 0.29')"
ps="expr('2*int((@nf + 2)/2) * (@W / @nf + 0.29)')"
nrd="expr('0.29 / @W ')" nrs="expr('0.29 / @W ')"
sa=0 sb=0 sd=0
model=nfet_01v8_lvt
spiceprefix=X
}
C {sky130_fd_pr/nfet_01v8_lvt.sym} 370 740 3 1 {name=M22
W=3
L=1
nf=1
mult=1
ad="expr('int((@nf + 1)/2) * @W / @nf * 0.29')"
pd="expr('2*int((@nf + 1)/2) * (@W / @nf + 0.29)')"
as="expr('int((@nf + 2)/2) * @W / @nf * 0.29')"
ps="expr('2*int((@nf + 2)/2) * (@W / @nf + 0.29)')"
nrd="expr('0.29 / @W ')" nrs="expr('0.29 / @W ')"
sa=0 sb=0 sd=0
model=nfet_01v8_lvt
spiceprefix=X
}
C {sky130_fd_pr/nfet_01v8_lvt.sym} 280 740 1 0 {name=M23
W=3
L=1
nf=1
mult=1
ad="expr('int((@nf + 1)/2) * @W / @nf * 0.29')"
pd="expr('2*int((@nf + 1)/2) * (@W / @nf + 0.29)')"
as="expr('int((@nf + 2)/2) * @W / @nf * 0.29')"
ps="expr('2*int((@nf + 2)/2) * (@W / @nf + 0.29)')"
nrd="expr('0.29 / @W ')" nrs="expr('0.29 / @W ')"
sa=0 sb=0 sd=0
model=nfet_01v8_lvt
spiceprefix=X
}
C {sky130_fd_pr/nfet_01v8_lvt.sym} 990 740 1 0 {name=M24
W=3
L=1
nf=1
mult=1
ad="expr('int((@nf + 1)/2) * @W / @nf * 0.29')"
pd="expr('2*int((@nf + 1)/2) * (@W / @nf + 0.29)')"
as="expr('int((@nf + 2)/2) * @W / @nf * 0.29')"
ps="expr('2*int((@nf + 2)/2) * (@W / @nf + 0.29)')"
nrd="expr('0.29 / @W ')" nrs="expr('0.29 / @W ')"
sa=0 sb=0 sd=0
model=nfet_01v8_lvt
spiceprefix=X
}
C {sky130_fd_pr/nfet_01v8_lvt.sym} 1070 740 3 1 {name=M25
W=3
L=1
nf=1
mult=1
ad="expr('int((@nf + 1)/2) * @W / @nf * 0.29')"
pd="expr('2*int((@nf + 1)/2) * (@W / @nf + 0.29)')"
as="expr('int((@nf + 2)/2) * @W / @nf * 0.29')"
ps="expr('2*int((@nf + 2)/2) * (@W / @nf + 0.29)')"
nrd="expr('0.29 / @W ')" nrs="expr('0.29 / @W ')"
sa=0 sb=0 sd=0
model=nfet_01v8_lvt
spiceprefix=X
}
C {sky130_fd_pr/nfet_01v8_lvt.sym} 1150 740 1 0 {name=M26
W=3
L=1
nf=1
mult=1
ad="expr('int((@nf + 1)/2) * @W / @nf * 0.29')"
pd="expr('2*int((@nf + 1)/2) * (@W / @nf + 0.29)')"
as="expr('int((@nf + 2)/2) * @W / @nf * 0.29')"
ps="expr('2*int((@nf + 2)/2) * (@W / @nf + 0.29)')"
nrd="expr('0.29 / @W ')" nrs="expr('0.29 / @W ')"
sa=0 sb=0 sd=0
model=nfet_01v8_lvt
spiceprefix=X
}
C {sky130_fd_pr/nfet_01v8_lvt.sym} 1230 740 3 1 {name=M27
W=3
L=1
nf=1
mult=1
ad="expr('int((@nf + 1)/2) * @W / @nf * 0.29')"
pd="expr('2*int((@nf + 1)/2) * (@W / @nf + 0.29)')"
as="expr('int((@nf + 2)/2) * @W / @nf * 0.29')"
ps="expr('2*int((@nf + 2)/2) * (@W / @nf + 0.29)')"
nrd="expr('0.29 / @W ')" nrs="expr('0.29 / @W ')"
sa=0 sb=0 sd=0
model=nfet_01v8_lvt
spiceprefix=X
}
C {sky130_fd_pr/nfet_01v8_lvt.sym} 1310 740 1 0 {name=M28
W=3
L=1
nf=1
mult=1
ad="expr('int((@nf + 1)/2) * @W / @nf * 0.29')"
pd="expr('2*int((@nf + 1)/2) * (@W / @nf + 0.29)')"
as="expr('int((@nf + 2)/2) * @W / @nf * 0.29')"
ps="expr('2*int((@nf + 2)/2) * (@W / @nf + 0.29)')"
nrd="expr('0.29 / @W ')" nrs="expr('0.29 / @W ')"
sa=0 sb=0 sd=0
model=nfet_01v8_lvt
spiceprefix=X
}
C {sky130_fd_pr/nfet_01v8_lvt.sym} 1400 740 3 1 {name=M29
W=3
L=1
nf=1
mult=1
ad="expr('int((@nf + 1)/2) * @W / @nf * 0.29')"
pd="expr('2*int((@nf + 1)/2) * (@W / @nf + 0.29)')"
as="expr('int((@nf + 2)/2) * @W / @nf * 0.29')"
ps="expr('2*int((@nf + 2)/2) * (@W / @nf + 0.29)')"
nrd="expr('0.29 / @W ')" nrs="expr('0.29 / @W ')"
sa=0 sb=0 sd=0
model=nfet_01v8_lvt
spiceprefix=X
}
C {sky130_fd_pr/nfet_01v8_lvt.sym} 200 740 3 1 {name=M30
W=3
L=1
nf=1
mult=1
ad="expr('int((@nf + 1)/2) * @W / @nf * 0.29')"
pd="expr('2*int((@nf + 1)/2) * (@W / @nf + 0.29)')"
as="expr('int((@nf + 2)/2) * @W / @nf * 0.29')"
ps="expr('2*int((@nf + 2)/2) * (@W / @nf + 0.29)')"
nrd="expr('0.29 / @W ')" nrs="expr('0.29 / @W ')"
sa=0 sb=0 sd=0
model=nfet_01v8_lvt
spiceprefix=X
}
C {sky130_fd_pr/nfet_01v8_lvt.sym} 1480 740 1 0 {name=M31
W=3
L=1
nf=1
mult=1
ad="expr('int((@nf + 1)/2) * @W / @nf * 0.29')"
pd="expr('2*int((@nf + 1)/2) * (@W / @nf + 0.29)')"
as="expr('int((@nf + 2)/2) * @W / @nf * 0.29')"
ps="expr('2*int((@nf + 2)/2) * (@W / @nf + 0.29)')"
nrd="expr('0.29 / @W ')" nrs="expr('0.29 / @W ')"
sa=0 sb=0 sd=0
model=nfet_01v8_lvt
spiceprefix=X
}
C {sky130_fd_pr/nfet_01v8_lvt.sym} 790 600 3 0 {name=M32
W=3
L=1
nf=1
mult=1
ad="expr('int((@nf + 1)/2) * @W / @nf * 0.29')"
pd="expr('2*int((@nf + 1)/2) * (@W / @nf + 0.29)')"
as="expr('int((@nf + 2)/2) * @W / @nf * 0.29')"
ps="expr('2*int((@nf + 2)/2) * (@W / @nf + 0.29)')"
nrd="expr('0.29 / @W ')" nrs="expr('0.29 / @W ')"
sa=0 sb=0 sd=0
model=nfet_01v8_lvt
spiceprefix=X
}
C {sky130_fd_pr/nfet_01v8_lvt.sym} 710 600 1 1 {name=M33
W=3
L=1
nf=1
mult=1
ad="expr('int((@nf + 1)/2) * @W / @nf * 0.29')"
pd="expr('2*int((@nf + 1)/2) * (@W / @nf + 0.29)')"
as="expr('int((@nf + 2)/2) * @W / @nf * 0.29')"
ps="expr('2*int((@nf + 2)/2) * (@W / @nf + 0.29)')"
nrd="expr('0.29 / @W ')" nrs="expr('0.29 / @W ')"
sa=0 sb=0 sd=0
model=nfet_01v8_lvt
spiceprefix=X
}
C {sky130_fd_pr/nfet_01v8_lvt.sym} 630 600 3 0 {name=M34
W=3
L=1
nf=1
mult=1
ad="expr('int((@nf + 1)/2) * @W / @nf * 0.29')"
pd="expr('2*int((@nf + 1)/2) * (@W / @nf + 0.29)')"
as="expr('int((@nf + 2)/2) * @W / @nf * 0.29')"
ps="expr('2*int((@nf + 2)/2) * (@W / @nf + 0.29)')"
nrd="expr('0.29 / @W ')" nrs="expr('0.29 / @W ')"
sa=0 sb=0 sd=0
model=nfet_01v8_lvt
spiceprefix=X
}
C {sky130_fd_pr/nfet_01v8_lvt.sym} 550 600 1 1 {name=M35
W=3
L=1
nf=1
mult=1
ad="expr('int((@nf + 1)/2) * @W / @nf * 0.29')"
pd="expr('2*int((@nf + 1)/2) * (@W / @nf + 0.29)')"
as="expr('int((@nf + 2)/2) * @W / @nf * 0.29')"
ps="expr('2*int((@nf + 2)/2) * (@W / @nf + 0.29)')"
nrd="expr('0.29 / @W ')" nrs="expr('0.29 / @W ')"
sa=0 sb=0 sd=0
model=nfet_01v8_lvt
spiceprefix=X
}
C {sky130_fd_pr/nfet_01v8_lvt.sym} 470 600 3 0 {name=M36
W=3
L=1
nf=1
mult=1
ad="expr('int((@nf + 1)/2) * @W / @nf * 0.29')"
pd="expr('2*int((@nf + 1)/2) * (@W / @nf + 0.29)')"
as="expr('int((@nf + 2)/2) * @W / @nf * 0.29')"
ps="expr('2*int((@nf + 2)/2) * (@W / @nf + 0.29)')"
nrd="expr('0.29 / @W ')" nrs="expr('0.29 / @W ')"
sa=0 sb=0 sd=0
model=nfet_01v8_lvt
spiceprefix=X
}
C {sky130_fd_pr/nfet_01v8_lvt.sym} 380 600 1 1 {name=M37
W=3
L=1
nf=1
mult=1
ad="expr('int((@nf + 1)/2) * @W / @nf * 0.29')"
pd="expr('2*int((@nf + 1)/2) * (@W / @nf + 0.29)')"
as="expr('int((@nf + 2)/2) * @W / @nf * 0.29')"
ps="expr('2*int((@nf + 2)/2) * (@W / @nf + 0.29)')"
nrd="expr('0.29 / @W ')" nrs="expr('0.29 / @W ')"
sa=0 sb=0 sd=0
model=nfet_01v8_lvt
spiceprefix=X
}
C {sky130_fd_pr/nfet_01v8_lvt.sym} 890 600 1 1 {name=M38
W=3
L=1
nf=1
mult=1
ad="expr('int((@nf + 1)/2) * @W / @nf * 0.29')"
pd="expr('2*int((@nf + 1)/2) * (@W / @nf + 0.29)')"
as="expr('int((@nf + 2)/2) * @W / @nf * 0.29')"
ps="expr('2*int((@nf + 2)/2) * (@W / @nf + 0.29)')"
nrd="expr('0.29 / @W ')" nrs="expr('0.29 / @W ')"
sa=0 sb=0 sd=0
model=nfet_01v8_lvt
spiceprefix=X
}
C {sky130_fd_pr/nfet_01v8_lvt.sym} 970 600 3 0 {name=M39
W=3
L=1
nf=1
mult=1
ad="expr('int((@nf + 1)/2) * @W / @nf * 0.29')"
pd="expr('2*int((@nf + 1)/2) * (@W / @nf + 0.29)')"
as="expr('int((@nf + 2)/2) * @W / @nf * 0.29')"
ps="expr('2*int((@nf + 2)/2) * (@W / @nf + 0.29)')"
nrd="expr('0.29 / @W ')" nrs="expr('0.29 / @W ')"
sa=0 sb=0 sd=0
model=nfet_01v8_lvt
spiceprefix=X
}
C {sky130_fd_pr/nfet_01v8_lvt.sym} 1050 600 1 1 {name=M40
W=3
L=1
nf=1
mult=1
ad="expr('int((@nf + 1)/2) * @W / @nf * 0.29')"
pd="expr('2*int((@nf + 1)/2) * (@W / @nf + 0.29)')"
as="expr('int((@nf + 2)/2) * @W / @nf * 0.29')"
ps="expr('2*int((@nf + 2)/2) * (@W / @nf + 0.29)')"
nrd="expr('0.29 / @W ')" nrs="expr('0.29 / @W ')"
sa=0 sb=0 sd=0
model=nfet_01v8_lvt
spiceprefix=X
}
C {sky130_fd_pr/nfet_01v8_lvt.sym} 1130 600 3 0 {name=M41
W=3
L=1
nf=1
mult=1
ad="expr('int((@nf + 1)/2) * @W / @nf * 0.29')"
pd="expr('2*int((@nf + 1)/2) * (@W / @nf + 0.29)')"
as="expr('int((@nf + 2)/2) * @W / @nf * 0.29')"
ps="expr('2*int((@nf + 2)/2) * (@W / @nf + 0.29)')"
nrd="expr('0.29 / @W ')" nrs="expr('0.29 / @W ')"
sa=0 sb=0 sd=0
model=nfet_01v8_lvt
spiceprefix=X
}
C {sky130_fd_pr/nfet_01v8_lvt.sym} 1210 600 1 1 {name=M42
W=3
L=1
nf=1
mult=1
ad="expr('int((@nf + 1)/2) * @W / @nf * 0.29')"
pd="expr('2*int((@nf + 1)/2) * (@W / @nf + 0.29)')"
as="expr('int((@nf + 2)/2) * @W / @nf * 0.29')"
ps="expr('2*int((@nf + 2)/2) * (@W / @nf + 0.29)')"
nrd="expr('0.29 / @W ')" nrs="expr('0.29 / @W ')"
sa=0 sb=0 sd=0
model=nfet_01v8_lvt
spiceprefix=X
}
C {sky130_fd_pr/nfet_01v8_lvt.sym} 1300 600 3 0 {name=M43
W=3
L=1
nf=1
mult=1
ad="expr('int((@nf + 1)/2) * @W / @nf * 0.29')"
pd="expr('2*int((@nf + 1)/2) * (@W / @nf + 0.29)')"
as="expr('int((@nf + 2)/2) * @W / @nf * 0.29')"
ps="expr('2*int((@nf + 2)/2) * (@W / @nf + 0.29)')"
nrd="expr('0.29 / @W ')" nrs="expr('0.29 / @W ')"
sa=0 sb=0 sd=0
model=nfet_01v8_lvt
spiceprefix=X
}
C {sky130_fd_pr/nfet_01v8_lvt.sym} 1380 600 1 1 {name=M44
W=3
L=1
nf=1
mult=1
ad="expr('int((@nf + 1)/2) * @W / @nf * 0.29')"
pd="expr('2*int((@nf + 1)/2) * (@W / @nf + 0.29)')"
as="expr('int((@nf + 2)/2) * @W / @nf * 0.29')"
ps="expr('2*int((@nf + 2)/2) * (@W / @nf + 0.29)')"
nrd="expr('0.29 / @W ')" nrs="expr('0.29 / @W ')"
sa=0 sb=0 sd=0
model=nfet_01v8_lvt
spiceprefix=X
}
C {sky130_fd_pr/nfet_01v8_lvt.sym} 290 600 3 0 {name=M45
W=3
L=1
nf=1
mult=1
ad="expr('int((@nf + 1)/2) * @W / @nf * 0.29')"
pd="expr('2*int((@nf + 1)/2) * (@W / @nf + 0.29)')"
as="expr('int((@nf + 2)/2) * @W / @nf * 0.29')"
ps="expr('2*int((@nf + 2)/2) * (@W / @nf + 0.29)')"
nrd="expr('0.29 / @W ')" nrs="expr('0.29 / @W ')"
sa=0 sb=0 sd=0
model=nfet_01v8_lvt
spiceprefix=X
}
C {sky130_fd_pr/nfet_01v8_lvt.sym} 200 600 3 0 {name=M46
W=3
L=1
nf=1
mult=1
ad="expr('int((@nf + 1)/2) * @W / @nf * 0.29')"
pd="expr('2*int((@nf + 1)/2) * (@W / @nf + 0.29)')"
as="expr('int((@nf + 2)/2) * @W / @nf * 0.29')"
ps="expr('2*int((@nf + 2)/2) * (@W / @nf + 0.29)')"
nrd="expr('0.29 / @W ')" nrs="expr('0.29 / @W ')"
sa=0 sb=0 sd=0
model=nfet_01v8_lvt
spiceprefix=X
}
C {sky130_fd_pr/nfet_01v8_lvt.sym} 1460 600 1 1 {name=M47
W=3
L=1
nf=1
mult=1
ad="expr('int((@nf + 1)/2) * @W / @nf * 0.29')"
pd="expr('2*int((@nf + 1)/2) * (@W / @nf + 0.29)')"
as="expr('int((@nf + 2)/2) * @W / @nf * 0.29')"
ps="expr('2*int((@nf + 2)/2) * (@W / @nf + 0.29)')"
nrd="expr('0.29 / @W ')" nrs="expr('0.29 / @W ')"
sa=0 sb=0 sd=0
model=nfet_01v8_lvt
spiceprefix=X
}
C {sky130_fd_pr/nfet_01v8_lvt.sym} 790 880 3 1 {name=M48
W=3
L=1
nf=1
mult=1
ad="expr('int((@nf + 1)/2) * @W / @nf * 0.29')"
pd="expr('2*int((@nf + 1)/2) * (@W / @nf + 0.29)')"
as="expr('int((@nf + 2)/2) * @W / @nf * 0.29')"
ps="expr('2*int((@nf + 2)/2) * (@W / @nf + 0.29)')"
nrd="expr('0.29 / @W ')" nrs="expr('0.29 / @W ')"
sa=0 sb=0 sd=0
model=nfet_01v8_lvt
spiceprefix=X
}
C {sky130_fd_pr/nfet_01v8_lvt.sym} 710 880 1 0 {name=M49
W=3
L=1
nf=1
mult=1
ad="expr('int((@nf + 1)/2) * @W / @nf * 0.29')"
pd="expr('2*int((@nf + 1)/2) * (@W / @nf + 0.29)')"
as="expr('int((@nf + 2)/2) * @W / @nf * 0.29')"
ps="expr('2*int((@nf + 2)/2) * (@W / @nf + 0.29)')"
nrd="expr('0.29 / @W ')" nrs="expr('0.29 / @W ')"
sa=0 sb=0 sd=0
model=nfet_01v8_lvt
spiceprefix=X
}
C {sky130_fd_pr/nfet_01v8_lvt.sym} 630 880 3 1 {name=M50
W=3
L=1
nf=1
mult=1
ad="expr('int((@nf + 1)/2) * @W / @nf * 0.29')"
pd="expr('2*int((@nf + 1)/2) * (@W / @nf + 0.29)')"
as="expr('int((@nf + 2)/2) * @W / @nf * 0.29')"
ps="expr('2*int((@nf + 2)/2) * (@W / @nf + 0.29)')"
nrd="expr('0.29 / @W ')" nrs="expr('0.29 / @W ')"
sa=0 sb=0 sd=0
model=nfet_01v8_lvt
spiceprefix=X
}
C {sky130_fd_pr/nfet_01v8_lvt.sym} 550 880 1 0 {name=M51
W=3
L=1
nf=1
mult=1
ad="expr('int((@nf + 1)/2) * @W / @nf * 0.29')"
pd="expr('2*int((@nf + 1)/2) * (@W / @nf + 0.29)')"
as="expr('int((@nf + 2)/2) * @W / @nf * 0.29')"
ps="expr('2*int((@nf + 2)/2) * (@W / @nf + 0.29)')"
nrd="expr('0.29 / @W ')" nrs="expr('0.29 / @W ')"
sa=0 sb=0 sd=0
model=nfet_01v8_lvt
spiceprefix=X
}
C {sky130_fd_pr/nfet_01v8_lvt.sym} 470 880 3 1 {name=M52
W=3
L=1
nf=1
mult=1
ad="expr('int((@nf + 1)/2) * @W / @nf * 0.29')"
pd="expr('2*int((@nf + 1)/2) * (@W / @nf + 0.29)')"
as="expr('int((@nf + 2)/2) * @W / @nf * 0.29')"
ps="expr('2*int((@nf + 2)/2) * (@W / @nf + 0.29)')"
nrd="expr('0.29 / @W ')" nrs="expr('0.29 / @W ')"
sa=0 sb=0 sd=0
model=nfet_01v8_lvt
spiceprefix=X
}
C {sky130_fd_pr/nfet_01v8_lvt.sym} 380 880 1 0 {name=M53
W=3
L=1
nf=1
mult=1
ad="expr('int((@nf + 1)/2) * @W / @nf * 0.29')"
pd="expr('2*int((@nf + 1)/2) * (@W / @nf + 0.29)')"
as="expr('int((@nf + 2)/2) * @W / @nf * 0.29')"
ps="expr('2*int((@nf + 2)/2) * (@W / @nf + 0.29)')"
nrd="expr('0.29 / @W ')" nrs="expr('0.29 / @W ')"
sa=0 sb=0 sd=0
model=nfet_01v8_lvt
spiceprefix=X
}
C {sky130_fd_pr/nfet_01v8_lvt.sym} 890 880 1 0 {name=M54
W=3
L=1
nf=1
mult=1
ad="expr('int((@nf + 1)/2) * @W / @nf * 0.29')"
pd="expr('2*int((@nf + 1)/2) * (@W / @nf + 0.29)')"
as="expr('int((@nf + 2)/2) * @W / @nf * 0.29')"
ps="expr('2*int((@nf + 2)/2) * (@W / @nf + 0.29)')"
nrd="expr('0.29 / @W ')" nrs="expr('0.29 / @W ')"
sa=0 sb=0 sd=0
model=nfet_01v8_lvt
spiceprefix=X
}
C {sky130_fd_pr/nfet_01v8_lvt.sym} 970 880 3 1 {name=M55
W=3
L=1
nf=1
mult=1
ad="expr('int((@nf + 1)/2) * @W / @nf * 0.29')"
pd="expr('2*int((@nf + 1)/2) * (@W / @nf + 0.29)')"
as="expr('int((@nf + 2)/2) * @W / @nf * 0.29')"
ps="expr('2*int((@nf + 2)/2) * (@W / @nf + 0.29)')"
nrd="expr('0.29 / @W ')" nrs="expr('0.29 / @W ')"
sa=0 sb=0 sd=0
model=nfet_01v8_lvt
spiceprefix=X
}
C {sky130_fd_pr/nfet_01v8_lvt.sym} 1050 880 1 0 {name=M56
W=3
L=1
nf=1
mult=1
ad="expr('int((@nf + 1)/2) * @W / @nf * 0.29')"
pd="expr('2*int((@nf + 1)/2) * (@W / @nf + 0.29)')"
as="expr('int((@nf + 2)/2) * @W / @nf * 0.29')"
ps="expr('2*int((@nf + 2)/2) * (@W / @nf + 0.29)')"
nrd="expr('0.29 / @W ')" nrs="expr('0.29 / @W ')"
sa=0 sb=0 sd=0
model=nfet_01v8_lvt
spiceprefix=X
}
C {sky130_fd_pr/nfet_01v8_lvt.sym} 1130 880 3 1 {name=M57
W=3
L=1
nf=1
mult=1
ad="expr('int((@nf + 1)/2) * @W / @nf * 0.29')"
pd="expr('2*int((@nf + 1)/2) * (@W / @nf + 0.29)')"
as="expr('int((@nf + 2)/2) * @W / @nf * 0.29')"
ps="expr('2*int((@nf + 2)/2) * (@W / @nf + 0.29)')"
nrd="expr('0.29 / @W ')" nrs="expr('0.29 / @W ')"
sa=0 sb=0 sd=0
model=nfet_01v8_lvt
spiceprefix=X
}
C {sky130_fd_pr/nfet_01v8_lvt.sym} 1210 880 1 0 {name=M58
W=3
L=1
nf=1
mult=1
ad="expr('int((@nf + 1)/2) * @W / @nf * 0.29')"
pd="expr('2*int((@nf + 1)/2) * (@W / @nf + 0.29)')"
as="expr('int((@nf + 2)/2) * @W / @nf * 0.29')"
ps="expr('2*int((@nf + 2)/2) * (@W / @nf + 0.29)')"
nrd="expr('0.29 / @W ')" nrs="expr('0.29 / @W ')"
sa=0 sb=0 sd=0
model=nfet_01v8_lvt
spiceprefix=X
}
C {sky130_fd_pr/nfet_01v8_lvt.sym} 1300 880 3 1 {name=M59
W=3
L=1
nf=1
mult=1
ad="expr('int((@nf + 1)/2) * @W / @nf * 0.29')"
pd="expr('2*int((@nf + 1)/2) * (@W / @nf + 0.29)')"
as="expr('int((@nf + 2)/2) * @W / @nf * 0.29')"
ps="expr('2*int((@nf + 2)/2) * (@W / @nf + 0.29)')"
nrd="expr('0.29 / @W ')" nrs="expr('0.29 / @W ')"
sa=0 sb=0 sd=0
model=nfet_01v8_lvt
spiceprefix=X
}
C {sky130_fd_pr/nfet_01v8_lvt.sym} 1380 880 1 0 {name=M60
W=3
L=1
nf=1
mult=1
ad="expr('int((@nf + 1)/2) * @W / @nf * 0.29')"
pd="expr('2*int((@nf + 1)/2) * (@W / @nf + 0.29)')"
as="expr('int((@nf + 2)/2) * @W / @nf * 0.29')"
ps="expr('2*int((@nf + 2)/2) * (@W / @nf + 0.29)')"
nrd="expr('0.29 / @W ')" nrs="expr('0.29 / @W ')"
sa=0 sb=0 sd=0
model=nfet_01v8_lvt
spiceprefix=X
}
C {sky130_fd_pr/nfet_01v8_lvt.sym} 290 880 3 1 {name=M61
W=3
L=1
nf=1
mult=1
ad="expr('int((@nf + 1)/2) * @W / @nf * 0.29')"
pd="expr('2*int((@nf + 1)/2) * (@W / @nf + 0.29)')"
as="expr('int((@nf + 2)/2) * @W / @nf * 0.29')"
ps="expr('2*int((@nf + 2)/2) * (@W / @nf + 0.29)')"
nrd="expr('0.29 / @W ')" nrs="expr('0.29 / @W ')"
sa=0 sb=0 sd=0
model=nfet_01v8_lvt
spiceprefix=X
}
C {sky130_fd_pr/nfet_01v8_lvt.sym} 200 880 3 1 {name=M62
W=3
L=1
nf=1
mult=1
ad="expr('int((@nf + 1)/2) * @W / @nf * 0.29')"
pd="expr('2*int((@nf + 1)/2) * (@W / @nf + 0.29)')"
as="expr('int((@nf + 2)/2) * @W / @nf * 0.29')"
ps="expr('2*int((@nf + 2)/2) * (@W / @nf + 0.29)')"
nrd="expr('0.29 / @W ')" nrs="expr('0.29 / @W ')"
sa=0 sb=0 sd=0
model=nfet_01v8_lvt
spiceprefix=X
}
C {sky130_fd_pr/nfet_01v8_lvt.sym} 1460 880 1 0 {name=M63
W=3
L=1
nf=1
mult=1
ad="expr('int((@nf + 1)/2) * @W / @nf * 0.29')"
pd="expr('2*int((@nf + 1)/2) * (@W / @nf + 0.29)')"
as="expr('int((@nf + 2)/2) * @W / @nf * 0.29')"
ps="expr('2*int((@nf + 2)/2) * (@W / @nf + 0.29)')"
nrd="expr('0.29 / @W ')" nrs="expr('0.29 / @W ')"
sa=0 sb=0 sd=0
model=nfet_01v8_lvt
spiceprefix=X
}
C {sky130_fd_pr/pfet_01v8.sym} 830 -2040 3 0 {name=M68
W=1
L=0.4
nf=1
mult=1
ad="'int((nf+1)/2) * W/nf * 0.29'" 
pd="'2*int((nf+1)/2) * (W/nf + 0.29)'"
as="'int((nf+2)/2) * W/nf * 0.29'" 
ps="'2*int((nf+2)/2) * (W/nf + 0.29)'"
nrd="'0.29 / W'" nrs="'0.29 / W'"
sa=0 sb=0 sd=0
model=pfet_01v8
spiceprefix=X
}
C {sky130_fd_pr/pfet_01v8.sym} 910 -2040 1 1 {name=M69
W=1
L=0.4
nf=1
mult=1
ad="'int((nf+1)/2) * W/nf * 0.29'" 
pd="'2*int((nf+1)/2) * (W/nf + 0.29)'"
as="'int((nf+2)/2) * W/nf * 0.29'" 
ps="'2*int((nf+2)/2) * (W/nf + 0.29)'"
nrd="'0.29 / W'" nrs="'0.29 / W'"
sa=0 sb=0 sd=0
model=pfet_01v8
spiceprefix=X
}
C {sky130_fd_pr/pfet_01v8.sym} 1020 -1950 3 1 {name=M70
W=1
L=0.4
nf=1
mult=1
ad="'int((nf+1)/2) * W/nf * 0.29'" 
pd="'2*int((nf+1)/2) * (W/nf + 0.29)'"
as="'int((nf+2)/2) * W/nf * 0.29'" 
ps="'2*int((nf+2)/2) * (W/nf + 0.29)'"
nrd="'0.29 / W'" nrs="'0.29 / W'"
sa=0 sb=0 sd=0
model=pfet_01v8
spiceprefix=X
}
C {sky130_fd_pr/pfet_01v8.sym} 1090 -1950 1 0 {name=M71
W=1
L=0.4
nf=1
mult=1
ad="'int((nf+1)/2) * W/nf * 0.29'" 
pd="'2*int((nf+1)/2) * (W/nf + 0.29)'"
as="'int((nf+2)/2) * W/nf * 0.29'" 
ps="'2*int((nf+2)/2) * (W/nf + 0.29)'"
nrd="'0.29 / W'" nrs="'0.29 / W'"
sa=0 sb=0 sd=0
model=pfet_01v8
spiceprefix=X
}
C {sky130_fd_pr/pfet_01v8.sym} 830 -1950 3 1 {name=M72
W=1
L=0.4
nf=1
mult=1
ad="'int((nf+1)/2) * W/nf * 0.29'" 
pd="'2*int((nf+1)/2) * (W/nf + 0.29)'"
as="'int((nf+2)/2) * W/nf * 0.29'" 
ps="'2*int((nf+2)/2) * (W/nf + 0.29)'"
nrd="'0.29 / W'" nrs="'0.29 / W'"
sa=0 sb=0 sd=0
model=pfet_01v8
spiceprefix=X
}
C {sky130_fd_pr/pfet_01v8.sym} 900 -1950 1 0 {name=M73
W=1
L=0.4
nf=1
mult=1
ad="'int((nf+1)/2) * W/nf * 0.29'" 
pd="'2*int((nf+1)/2) * (W/nf + 0.29)'"
as="'int((nf+2)/2) * W/nf * 0.29'" 
ps="'2*int((nf+2)/2) * (W/nf + 0.29)'"
nrd="'0.29 / W'" nrs="'0.29 / W'"
sa=0 sb=0 sd=0
model=pfet_01v8
spiceprefix=X
}
C {sky130_fd_pr/pfet_01v8.sym} 1020 -2040 3 0 {name=M74
W=1
L=0.4
nf=1
mult=1
ad="'int((nf+1)/2) * W/nf * 0.29'" 
pd="'2*int((nf+1)/2) * (W/nf + 0.29)'"
as="'int((nf+2)/2) * W/nf * 0.29'" 
ps="'2*int((nf+2)/2) * (W/nf + 0.29)'"
nrd="'0.29 / W'" nrs="'0.29 / W'"
sa=0 sb=0 sd=0
model=pfet_01v8
spiceprefix=X
}
C {sky130_fd_pr/pfet_01v8.sym} 1090 -2040 1 1 {name=M75
W=1
L=0.4
nf=1
mult=1
ad="'int((nf+1)/2) * W/nf * 0.29'" 
pd="'2*int((nf+1)/2) * (W/nf + 0.29)'"
as="'int((nf+2)/2) * W/nf * 0.29'" 
ps="'2*int((nf+2)/2) * (W/nf + 0.29)'"
nrd="'0.29 / W'" nrs="'0.29 / W'"
sa=0 sb=0 sd=0
model=pfet_01v8
spiceprefix=X
}
C {sky130_fd_pr/pfet_01v8.sym} 830 -2180 1 1 {name=M76
W=1
L=0.4
nf=1
mult=1
ad="'int((nf+1)/2) * W/nf * 0.29'" 
pd="'2*int((nf+1)/2) * (W/nf + 0.29)'"
as="'int((nf+2)/2) * W/nf * 0.29'" 
ps="'2*int((nf+2)/2) * (W/nf + 0.29)'"
nrd="'0.29 / W'" nrs="'0.29 / W'"
sa=0 sb=0 sd=0
model=pfet_01v8
spiceprefix=X
}
C {sky130_fd_pr/pfet_01v8.sym} 910 -2180 3 0 {name=M78
W=1
L=0.4
nf=1
mult=1
ad="'int((nf+1)/2) * W/nf * 0.29'" 
pd="'2*int((nf+1)/2) * (W/nf + 0.29)'"
as="'int((nf+2)/2) * W/nf * 0.29'" 
ps="'2*int((nf+2)/2) * (W/nf + 0.29)'"
nrd="'0.29 / W'" nrs="'0.29 / W'"
sa=0 sb=0 sd=0
model=pfet_01v8
spiceprefix=X
}
C {sky130_fd_pr/pfet_01v8.sym} 1020 -2180 1 1 {name=M79
W=1
L=0.4
nf=1
mult=1
ad="'int((nf+1)/2) * W/nf * 0.29'" 
pd="'2*int((nf+1)/2) * (W/nf + 0.29)'"
as="'int((nf+2)/2) * W/nf * 0.29'" 
ps="'2*int((nf+2)/2) * (W/nf + 0.29)'"
nrd="'0.29 / W'" nrs="'0.29 / W'"
sa=0 sb=0 sd=0
model=pfet_01v8
spiceprefix=X
}
C {sky130_fd_pr/pfet_01v8.sym} 1090 -2180 3 0 {name=M80
W=1
L=0.4
nf=1
mult=1
ad="'int((nf+1)/2) * W/nf * 0.29'" 
pd="'2*int((nf+1)/2) * (W/nf + 0.29)'"
as="'int((nf+2)/2) * W/nf * 0.29'" 
ps="'2*int((nf+2)/2) * (W/nf + 0.29)'"
nrd="'0.29 / W'" nrs="'0.29 / W'"
sa=0 sb=0 sd=0
model=pfet_01v8
spiceprefix=X
}
C {sky130_fd_pr/pfet_01v8.sym} 830 -1780 1 0 {name=M81
W=1
L=0.4
nf=1
mult=1
ad="'int((nf+1)/2) * W/nf * 0.29'" 
pd="'2*int((nf+1)/2) * (W/nf + 0.29)'"
as="'int((nf+2)/2) * W/nf * 0.29'" 
ps="'2*int((nf+2)/2) * (W/nf + 0.29)'"
nrd="'0.29 / W'" nrs="'0.29 / W'"
sa=0 sb=0 sd=0
model=pfet_01v8
spiceprefix=X
}
C {sky130_fd_pr/pfet_01v8.sym} 900 -1780 3 1 {name=M82
W=1
L=0.4
nf=1
mult=1
ad="'int((nf+1)/2) * W/nf * 0.29'" 
pd="'2*int((nf+1)/2) * (W/nf + 0.29)'"
as="'int((nf+2)/2) * W/nf * 0.29'" 
ps="'2*int((nf+2)/2) * (W/nf + 0.29)'"
nrd="'0.29 / W'" nrs="'0.29 / W'"
sa=0 sb=0 sd=0
model=pfet_01v8
spiceprefix=X
}
C {sky130_fd_pr/pfet_01v8.sym} 1020 -1780 1 0 {name=M83
W=1
L=0.4
nf=1
mult=1
ad="'int((nf+1)/2) * W/nf * 0.29'" 
pd="'2*int((nf+1)/2) * (W/nf + 0.29)'"
as="'int((nf+2)/2) * W/nf * 0.29'" 
ps="'2*int((nf+2)/2) * (W/nf + 0.29)'"
nrd="'0.29 / W'" nrs="'0.29 / W'"
sa=0 sb=0 sd=0
model=pfet_01v8
spiceprefix=X
}
C {sky130_fd_pr/pfet_01v8.sym} 1090 -1780 3 1 {name=M84
W=1
L=0.4
nf=1
mult=1
ad="'int((nf+1)/2) * W/nf * 0.29'" 
pd="'2*int((nf+1)/2) * (W/nf + 0.29)'"
as="'int((nf+2)/2) * W/nf * 0.29'" 
ps="'2*int((nf+2)/2) * (W/nf + 0.29)'"
nrd="'0.29 / W'" nrs="'0.29 / W'"
sa=0 sb=0 sd=0
model=pfet_01v8
spiceprefix=X
}
C {sky130_fd_pr/pfet_01v8.sym} 1170 -2180 1 1 {name=M87
W=1
L=0.4
nf=1
mult=1
ad="'int((nf+1)/2) * W/nf * 0.29'" 
pd="'2*int((nf+1)/2) * (W/nf + 0.29)'"
as="'int((nf+2)/2) * W/nf * 0.29'" 
ps="'2*int((nf+2)/2) * (W/nf + 0.29)'"
nrd="'0.29 / W'" nrs="'0.29 / W'"
sa=0 sb=0 sd=0
model=pfet_01v8
spiceprefix=X
}
C {sky130_fd_pr/pfet_01v8.sym} 1170 -1780 1 0 {name=M88
W=1
L=0.4
nf=1
mult=1
ad="'int((nf+1)/2) * W/nf * 0.29'" 
pd="'2*int((nf+1)/2) * (W/nf + 0.29)'"
as="'int((nf+2)/2) * W/nf * 0.29'" 
ps="'2*int((nf+2)/2) * (W/nf + 0.29)'"
nrd="'0.29 / W'" nrs="'0.29 / W'"
sa=0 sb=0 sd=0
model=pfet_01v8
spiceprefix=X
}
C {sky130_fd_pr/pfet_01v8.sym} 750 -2180 3 0 {name=M91
W=1
L=0.4
nf=1
mult=1
ad="'int((nf+1)/2) * W/nf * 0.29'" 
pd="'2*int((nf+1)/2) * (W/nf + 0.29)'"
as="'int((nf+2)/2) * W/nf * 0.29'" 
ps="'2*int((nf+2)/2) * (W/nf + 0.29)'"
nrd="'0.29 / W'" nrs="'0.29 / W'"
sa=0 sb=0 sd=0
model=pfet_01v8
spiceprefix=X
}
C {sky130_fd_pr/pfet_01v8.sym} 750 -1780 3 1 {name=M92
W=1
L=0.4
nf=1
mult=1
ad="'int((nf+1)/2) * W/nf * 0.29'" 
pd="'2*int((nf+1)/2) * (W/nf + 0.29)'"
as="'int((nf+2)/2) * W/nf * 0.29'" 
ps="'2*int((nf+2)/2) * (W/nf + 0.29)'"
nrd="'0.29 / W'" nrs="'0.29 / W'"
sa=0 sb=0 sd=0
model=pfet_01v8
spiceprefix=X
}
C {sky130_fd_pr/pfet_01v8.sym} 560 -1780 1 0 {name=M97
W=1
L=0.4
nf=1
mult=1
ad="'int((nf+1)/2) * W/nf * 0.29'" 
pd="'2*int((nf+1)/2) * (W/nf + 0.29)'"
as="'int((nf+2)/2) * W/nf * 0.29'" 
ps="'2*int((nf+2)/2) * (W/nf + 0.29)'"
nrd="'0.29 / W'" nrs="'0.29 / W'"
sa=0 sb=0 sd=0
model=pfet_01v8
spiceprefix=X
}
C {sky130_fd_pr/pfet_01v8.sym} 1440 -1780 3 1 {name=M98
W=1
L=0.4
nf=1
mult=1
ad="'int((nf+1)/2) * W/nf * 0.29'" 
pd="'2*int((nf+1)/2) * (W/nf + 0.29)'"
as="'int((nf+2)/2) * W/nf * 0.29'" 
ps="'2*int((nf+2)/2) * (W/nf + 0.29)'"
nrd="'0.29 / W'" nrs="'0.29 / W'"
sa=0 sb=0 sd=0
model=pfet_01v8
spiceprefix=X
}
C {sky130_fd_pr/pfet_01v8.sym} 670 -2180 1 1 {name=M99
W=1
L=0.4
nf=1
mult=1
ad="'int((nf+1)/2) * W/nf * 0.29'" 
pd="'2*int((nf+1)/2) * (W/nf + 0.29)'"
as="'int((nf+2)/2) * W/nf * 0.29'" 
ps="'2*int((nf+2)/2) * (W/nf + 0.29)'"
nrd="'0.29 / W'" nrs="'0.29 / W'"
sa=0 sb=0 sd=0
model=pfet_01v8
spiceprefix=X
}
C {sky130_fd_pr/pfet_01v8.sym} 1340 -2180 3 0 {name=M100
W=1
L=0.4
nf=1
mult=1
ad="'int((nf+1)/2) * W/nf * 0.29'" 
pd="'2*int((nf+1)/2) * (W/nf + 0.29)'"
as="'int((nf+2)/2) * W/nf * 0.29'" 
ps="'2*int((nf+2)/2) * (W/nf + 0.29)'"
nrd="'0.29 / W'" nrs="'0.29 / W'"
sa=0 sb=0 sd=0
model=pfet_01v8
spiceprefix=X
}
C {sky130_fd_pr/pfet_01v8.sym} 510 -2180 1 1 {name=M3
W=1
L=0.4
nf=1
mult=1
ad="'int((nf+1)/2) * W/nf * 0.29'" 
pd="'2*int((nf+1)/2) * (W/nf + 0.29)'"
as="'int((nf+2)/2) * W/nf * 0.29'" 
ps="'2*int((nf+2)/2) * (W/nf + 0.29)'"
nrd="'0.29 / W'" nrs="'0.29 / W'"
sa=0 sb=0 sd=0
model=pfet_01v8
spiceprefix=X
}
C {sky130_fd_pr/pfet_01v8.sym} 1250 -1780 3 1 {name=M4
W=1
L=0.4
nf=1
mult=1
ad="'int((nf+1)/2) * W/nf * 0.29'" 
pd="'2*int((nf+1)/2) * (W/nf + 0.29)'"
as="'int((nf+2)/2) * W/nf * 0.29'" 
ps="'2*int((nf+2)/2) * (W/nf + 0.29)'"
nrd="'0.29 / W'" nrs="'0.29 / W'"
sa=0 sb=0 sd=0
model=pfet_01v8
spiceprefix=X
}
C {sky130_fd_pr/pfet_01v8.sym} 590 -2180 3 0 {name=M7
W=1
L=0.4
nf=1
mult=1
ad="'int((nf+1)/2) * W/nf * 0.29'" 
pd="'2*int((nf+1)/2) * (W/nf + 0.29)'"
as="'int((nf+2)/2) * W/nf * 0.29'" 
ps="'2*int((nf+2)/2) * (W/nf + 0.29)'"
nrd="'0.29 / W'" nrs="'0.29 / W'"
sa=0 sb=0 sd=0
model=pfet_01v8
spiceprefix=X
}
C {sky130_fd_pr/pfet_01v8.sym} 1250 -2180 3 0 {name=M12
W=1
L=0.4
nf=1
mult=1
ad="'int((nf+1)/2) * W/nf * 0.29'" 
pd="'2*int((nf+1)/2) * (W/nf + 0.29)'"
as="'int((nf+2)/2) * W/nf * 0.29'" 
ps="'2*int((nf+2)/2) * (W/nf + 0.29)'"
nrd="'0.29 / W'" nrs="'0.29 / W'"
sa=0 sb=0 sd=0
model=pfet_01v8
spiceprefix=X
}
C {sky130_fd_pr/pfet_01v8.sym} 1410 -2180 3 0 {name=M64
W=1
L=0.4
nf=1
mult=1
ad="'int((nf+1)/2) * W/nf * 0.29'" 
pd="'2*int((nf+1)/2) * (W/nf + 0.29)'"
as="'int((nf+2)/2) * W/nf * 0.29'" 
ps="'2*int((nf+2)/2) * (W/nf + 0.29)'"
nrd="'0.29 / W'" nrs="'0.29 / W'"
sa=0 sb=0 sd=0
model=pfet_01v8
spiceprefix=X
}
C {sky130_fd_pr/pfet_01v8.sym} 750 -2040 1 1 {name=M65
W=1
L=0.4
nf=1
mult=1
ad="'int((nf+1)/2) * W/nf * 0.29'" 
pd="'2*int((nf+1)/2) * (W/nf + 0.29)'"
as="'int((nf+2)/2) * W/nf * 0.29'" 
ps="'2*int((nf+2)/2) * (W/nf + 0.29)'"
nrd="'0.29 / W'" nrs="'0.29 / W'"
sa=0 sb=0 sd=0
model=pfet_01v8
spiceprefix=X
}
C {sky130_fd_pr/pfet_01v8.sym} 1170 -2040 3 0 {name=M66
W=1
L=0.4
nf=1
mult=1
ad="'int((nf+1)/2) * W/nf * 0.29'" 
pd="'2*int((nf+1)/2) * (W/nf + 0.29)'"
as="'int((nf+2)/2) * W/nf * 0.29'" 
ps="'2*int((nf+2)/2) * (W/nf + 0.29)'"
nrd="'0.29 / W'" nrs="'0.29 / W'"
sa=0 sb=0 sd=0
model=pfet_01v8
spiceprefix=X
}
C {sky130_fd_pr/pfet_01v8.sym} 750 -1950 1 0 {name=M67
W=1
L=0.4
nf=1
mult=1
ad="'int((nf+1)/2) * W/nf * 0.29'" 
pd="'2*int((nf+1)/2) * (W/nf + 0.29)'"
as="'int((nf+2)/2) * W/nf * 0.29'" 
ps="'2*int((nf+2)/2) * (W/nf + 0.29)'"
nrd="'0.29 / W'" nrs="'0.29 / W'"
sa=0 sb=0 sd=0
model=pfet_01v8
spiceprefix=X
}
C {sky130_fd_pr/pfet_01v8.sym} 1170 -1950 3 1 {name=M77
W=1
L=0.4
nf=1
mult=1
ad="'int((nf+1)/2) * W/nf * 0.29'" 
pd="'2*int((nf+1)/2) * (W/nf + 0.29)'"
as="'int((nf+2)/2) * W/nf * 0.29'" 
ps="'2*int((nf+2)/2) * (W/nf + 0.29)'"
nrd="'0.29 / W'" nrs="'0.29 / W'"
sa=0 sb=0 sd=0
model=pfet_01v8
spiceprefix=X
}
C {sky130_fd_pr/pfet_01v8.sym} 660 -2040 1 1 {name=M85
W=1
L=0.4
nf=1
mult=1
ad="'int((nf+1)/2) * W/nf * 0.29'" 
pd="'2*int((nf+1)/2) * (W/nf + 0.29)'"
as="'int((nf+2)/2) * W/nf * 0.29'" 
ps="'2*int((nf+2)/2) * (W/nf + 0.29)'"
nrd="'0.29 / W'" nrs="'0.29 / W'"
sa=0 sb=0 sd=0
model=pfet_01v8
spiceprefix=X
}
C {sky130_fd_pr/pfet_01v8.sym} 580 -2040 3 0 {name=M86
W=1
L=0.4
nf=1
mult=1
ad="'int((nf+1)/2) * W/nf * 0.29'" 
pd="'2*int((nf+1)/2) * (W/nf + 0.29)'"
as="'int((nf+2)/2) * W/nf * 0.29'" 
ps="'2*int((nf+2)/2) * (W/nf + 0.29)'"
nrd="'0.29 / W'" nrs="'0.29 / W'"
sa=0 sb=0 sd=0
model=pfet_01v8
spiceprefix=X
}
C {sky130_fd_pr/pfet_01v8.sym} 500 -2040 1 1 {name=M89
W=1
L=0.4
nf=1
mult=1
ad="'int((nf+1)/2) * W/nf * 0.29'" 
pd="'2*int((nf+1)/2) * (W/nf + 0.29)'"
as="'int((nf+2)/2) * W/nf * 0.29'" 
ps="'2*int((nf+2)/2) * (W/nf + 0.29)'"
nrd="'0.29 / W'" nrs="'0.29 / W'"
sa=0 sb=0 sd=0
model=pfet_01v8
spiceprefix=X
}
C {sky130_fd_pr/pfet_01v8.sym} 1260 -2040 3 0 {name=M90
W=1
L=0.4
nf=1
mult=1
ad="'int((nf+1)/2) * W/nf * 0.29'" 
pd="'2*int((nf+1)/2) * (W/nf + 0.29)'"
as="'int((nf+2)/2) * W/nf * 0.29'" 
ps="'2*int((nf+2)/2) * (W/nf + 0.29)'"
nrd="'0.29 / W'" nrs="'0.29 / W'"
sa=0 sb=0 sd=0
model=pfet_01v8
spiceprefix=X
}
C {sky130_fd_pr/pfet_01v8.sym} 1340 -2040 1 1 {name=M93
W=1
L=0.4
nf=1
mult=1
ad="'int((nf+1)/2) * W/nf * 0.29'" 
pd="'2*int((nf+1)/2) * (W/nf + 0.29)'"
as="'int((nf+2)/2) * W/nf * 0.29'" 
ps="'2*int((nf+2)/2) * (W/nf + 0.29)'"
nrd="'0.29 / W'" nrs="'0.29 / W'"
sa=0 sb=0 sd=0
model=pfet_01v8
spiceprefix=X
}
C {sky130_fd_pr/pfet_01v8.sym} 1420 -2040 3 0 {name=M94
W=1
L=0.4
nf=1
mult=1
ad="'int((nf+1)/2) * W/nf * 0.29'" 
pd="'2*int((nf+1)/2) * (W/nf + 0.29)'"
as="'int((nf+2)/2) * W/nf * 0.29'" 
ps="'2*int((nf+2)/2) * (W/nf + 0.29)'"
nrd="'0.29 / W'" nrs="'0.29 / W'"
sa=0 sb=0 sd=0
model=pfet_01v8
spiceprefix=X
}
C {sky130_fd_pr/pfet_01v8.sym} 660 -1950 1 0 {name=M95
W=1
L=0.4
nf=1
mult=1
ad="'int((nf+1)/2) * W/nf * 0.29'" 
pd="'2*int((nf+1)/2) * (W/nf + 0.29)'"
as="'int((nf+2)/2) * W/nf * 0.29'" 
ps="'2*int((nf+2)/2) * (W/nf + 0.29)'"
nrd="'0.29 / W'" nrs="'0.29 / W'"
sa=0 sb=0 sd=0
model=pfet_01v8
spiceprefix=X
}
C {sky130_fd_pr/pfet_01v8.sym} 580 -1950 3 1 {name=M96
W=1
L=0.4
nf=1
mult=1
ad="'int((nf+1)/2) * W/nf * 0.29'" 
pd="'2*int((nf+1)/2) * (W/nf + 0.29)'"
as="'int((nf+2)/2) * W/nf * 0.29'" 
ps="'2*int((nf+2)/2) * (W/nf + 0.29)'"
nrd="'0.29 / W'" nrs="'0.29 / W'"
sa=0 sb=0 sd=0
model=pfet_01v8
spiceprefix=X
}
C {sky130_fd_pr/pfet_01v8.sym} 500 -1950 1 0 {name=M101
W=1
L=0.4
nf=1
mult=1
ad="'int((nf+1)/2) * W/nf * 0.29'" 
pd="'2*int((nf+1)/2) * (W/nf + 0.29)'"
as="'int((nf+2)/2) * W/nf * 0.29'" 
ps="'2*int((nf+2)/2) * (W/nf + 0.29)'"
nrd="'0.29 / W'" nrs="'0.29 / W'"
sa=0 sb=0 sd=0
model=pfet_01v8
spiceprefix=X
}
C {sky130_fd_pr/pfet_01v8.sym} 1260 -1950 3 1 {name=M102
W=1
L=0.4
nf=1
mult=1
ad="'int((nf+1)/2) * W/nf * 0.29'" 
pd="'2*int((nf+1)/2) * (W/nf + 0.29)'"
as="'int((nf+2)/2) * W/nf * 0.29'" 
ps="'2*int((nf+2)/2) * (W/nf + 0.29)'"
nrd="'0.29 / W'" nrs="'0.29 / W'"
sa=0 sb=0 sd=0
model=pfet_01v8
spiceprefix=X
}
C {sky130_fd_pr/pfet_01v8.sym} 1340 -1950 1 0 {name=M103
W=1
L=0.4
nf=1
mult=1
ad="'int((nf+1)/2) * W/nf * 0.29'" 
pd="'2*int((nf+1)/2) * (W/nf + 0.29)'"
as="'int((nf+2)/2) * W/nf * 0.29'" 
ps="'2*int((nf+2)/2) * (W/nf + 0.29)'"
nrd="'0.29 / W'" nrs="'0.29 / W'"
sa=0 sb=0 sd=0
model=pfet_01v8
spiceprefix=X
}
C {sky130_fd_pr/pfet_01v8.sym} 1420 -1950 3 1 {name=M104
W=1
L=0.4
nf=1
mult=1
ad="'int((nf+1)/2) * W/nf * 0.29'" 
pd="'2*int((nf+1)/2) * (W/nf + 0.29)'"
as="'int((nf+2)/2) * W/nf * 0.29'" 
ps="'2*int((nf+2)/2) * (W/nf + 0.29)'"
nrd="'0.29 / W'" nrs="'0.29 / W'"
sa=0 sb=0 sd=0
model=pfet_01v8
spiceprefix=X
}
C {sky130_fd_pr/pfet_01v8.sym} 670 -1780 1 0 {name=M105
W=1
L=0.4
nf=1
mult=1
ad="'int((nf+1)/2) * W/nf * 0.29'" 
pd="'2*int((nf+1)/2) * (W/nf + 0.29)'"
as="'int((nf+2)/2) * W/nf * 0.29'" 
ps="'2*int((nf+2)/2) * (W/nf + 0.29)'"
nrd="'0.29 / W'" nrs="'0.29 / W'"
sa=0 sb=0 sd=0
model=pfet_01v8
spiceprefix=X
}
C {sky130_fd_pr/pfet_01v8.sym} 490 -1780 1 0 {name=M106
W=1
L=0.4
nf=1
mult=1
ad="'int((nf+1)/2) * W/nf * 0.29'" 
pd="'2*int((nf+1)/2) * (W/nf + 0.29)'"
as="'int((nf+2)/2) * W/nf * 0.29'" 
ps="'2*int((nf+2)/2) * (W/nf + 0.29)'"
nrd="'0.29 / W'" nrs="'0.29 / W'"
sa=0 sb=0 sd=0
model=pfet_01v8
spiceprefix=X
}
C {sky130_fd_pr/pfet_01v8.sym} 1330 -1780 1 0 {name=M107
W=1
L=0.4
nf=1
mult=1
ad="'int((nf+1)/2) * W/nf * 0.29'" 
pd="'2*int((nf+1)/2) * (W/nf + 0.29)'"
as="'int((nf+2)/2) * W/nf * 0.29'" 
ps="'2*int((nf+2)/2) * (W/nf + 0.29)'"
nrd="'0.29 / W'" nrs="'0.29 / W'"
sa=0 sb=0 sd=0
model=pfet_01v8
spiceprefix=X
}
C {sky130_fd_pr/nfet_01v8_lvt.sym} 450 -810 3 1 {name=M1
W=7
L=1
nf=1
mult=1
ad="expr('int((@nf + 1)/2) * @W / @nf * 0.29')"
pd="expr('2*int((@nf + 1)/2) * (@W / @nf + 0.29)')"
as="expr('int((@nf + 2)/2) * @W / @nf * 0.29')"
ps="expr('2*int((@nf + 2)/2) * (@W / @nf + 0.29)')"
nrd="expr('0.29 / @W ')" nrs="expr('0.29 / @W ')"
sa=0 sb=0 sd=0
model=nfet_01v8_lvt
spiceprefix=X
}
C {sky130_fd_pr/nfet_01v8_lvt.sym} 520 -810 1 0 {name=M2
W=7
L=1
nf=1
mult=1
ad="expr('int((@nf + 1)/2) * @W / @nf * 0.29')"
pd="expr('2*int((@nf + 1)/2) * (@W / @nf + 0.29)')"
as="expr('int((@nf + 2)/2) * @W / @nf * 0.29')"
ps="expr('2*int((@nf + 2)/2) * (@W / @nf + 0.29)')"
nrd="expr('0.29 / @W ')" nrs="expr('0.29 / @W ')"
sa=0 sb=0 sd=0
model=nfet_01v8_lvt
spiceprefix=X
}
C {sky130_fd_pr/nfet_01v8_lvt.sym} 590 -810 3 1 {name=M108
W=7
L=1
nf=1
mult=1
ad="expr('int((@nf + 1)/2) * @W / @nf * 0.29')"
pd="expr('2*int((@nf + 1)/2) * (@W / @nf + 0.29)')"
as="expr('int((@nf + 2)/2) * @W / @nf * 0.29')"
ps="expr('2*int((@nf + 2)/2) * (@W / @nf + 0.29)')"
nrd="expr('0.29 / @W ')" nrs="expr('0.29 / @W ')"
sa=0 sb=0 sd=0
model=nfet_01v8_lvt
spiceprefix=X
}
C {sky130_fd_pr/nfet_01v8_lvt.sym} 660 -810 1 0 {name=M109
W=7
L=1
nf=1
mult=1
ad="expr('int((@nf + 1)/2) * @W / @nf * 0.29')"
pd="expr('2*int((@nf + 1)/2) * (@W / @nf + 0.29)')"
as="expr('int((@nf + 2)/2) * @W / @nf * 0.29')"
ps="expr('2*int((@nf + 2)/2) * (@W / @nf + 0.29)')"
nrd="expr('0.29 / @W ')" nrs="expr('0.29 / @W ')"
sa=0 sb=0 sd=0
model=nfet_01v8_lvt
spiceprefix=X
}
C {sky130_fd_pr/nfet_01v8_lvt.sym} 730 -810 3 1 {name=M110
W=7
L=1
nf=1
mult=1
ad="expr('int((@nf + 1)/2) * @W / @nf * 0.29')"
pd="expr('2*int((@nf + 1)/2) * (@W / @nf + 0.29)')"
as="expr('int((@nf + 2)/2) * @W / @nf * 0.29')"
ps="expr('2*int((@nf + 2)/2) * (@W / @nf + 0.29)')"
nrd="expr('0.29 / @W ')" nrs="expr('0.29 / @W ')"
sa=0 sb=0 sd=0
model=nfet_01v8_lvt
spiceprefix=X
}
C {sky130_fd_pr/nfet_01v8_lvt.sym} 800 -810 1 0 {name=M111
W=7
L=1
nf=1
mult=1
ad="expr('int((@nf + 1)/2) * @W / @nf * 0.29')"
pd="expr('2*int((@nf + 1)/2) * (@W / @nf + 0.29)')"
as="expr('int((@nf + 2)/2) * @W / @nf * 0.29')"
ps="expr('2*int((@nf + 2)/2) * (@W / @nf + 0.29)')"
nrd="expr('0.29 / @W ')" nrs="expr('0.29 / @W ')"
sa=0 sb=0 sd=0
model=nfet_01v8_lvt
spiceprefix=X
}
C {sky130_fd_pr/nfet_01v8_lvt.sym} 870 -810 3 1 {name=M112
W=7
L=1
nf=1
mult=1
ad="expr('int((@nf + 1)/2) * @W / @nf * 0.29')"
pd="expr('2*int((@nf + 1)/2) * (@W / @nf + 0.29)')"
as="expr('int((@nf + 2)/2) * @W / @nf * 0.29')"
ps="expr('2*int((@nf + 2)/2) * (@W / @nf + 0.29)')"
nrd="expr('0.29 / @W ')" nrs="expr('0.29 / @W ')"
sa=0 sb=0 sd=0
model=nfet_01v8_lvt
spiceprefix=X
}
C {sky130_fd_pr/nfet_01v8_lvt.sym} 940 -810 1 0 {name=M113
W=7
L=1
nf=1
mult=1
ad="expr('int((@nf + 1)/2) * @W / @nf * 0.29')"
pd="expr('2*int((@nf + 1)/2) * (@W / @nf + 0.29)')"
as="expr('int((@nf + 2)/2) * @W / @nf * 0.29')"
ps="expr('2*int((@nf + 2)/2) * (@W / @nf + 0.29)')"
nrd="expr('0.29 / @W ')" nrs="expr('0.29 / @W ')"
sa=0 sb=0 sd=0
model=nfet_01v8_lvt
spiceprefix=X
}
C {sky130_fd_pr/nfet_01v8_lvt.sym} 450 -590 3 0 {name=M114
W=7
L=1
nf=1
mult=1
ad="expr('int((@nf + 1)/2) * @W / @nf * 0.29')"
pd="expr('2*int((@nf + 1)/2) * (@W / @nf + 0.29)')"
as="expr('int((@nf + 2)/2) * @W / @nf * 0.29')"
ps="expr('2*int((@nf + 2)/2) * (@W / @nf + 0.29)')"
nrd="expr('0.29 / @W ')" nrs="expr('0.29 / @W ')"
sa=0 sb=0 sd=0
model=nfet_01v8_lvt
spiceprefix=X
}
C {sky130_fd_pr/nfet_01v8_lvt.sym} 520 -590 1 1 {name=M115
W=7
L=1
nf=1
mult=1
ad="expr('int((@nf + 1)/2) * @W / @nf * 0.29')"
pd="expr('2*int((@nf + 1)/2) * (@W / @nf + 0.29)')"
as="expr('int((@nf + 2)/2) * @W / @nf * 0.29')"
ps="expr('2*int((@nf + 2)/2) * (@W / @nf + 0.29)')"
nrd="expr('0.29 / @W ')" nrs="expr('0.29 / @W ')"
sa=0 sb=0 sd=0
model=nfet_01v8_lvt
spiceprefix=X
}
C {sky130_fd_pr/nfet_01v8_lvt.sym} 590 -590 3 0 {name=M116
W=7
L=1
nf=1
mult=1
ad="expr('int((@nf + 1)/2) * @W / @nf * 0.29')"
pd="expr('2*int((@nf + 1)/2) * (@W / @nf + 0.29)')"
as="expr('int((@nf + 2)/2) * @W / @nf * 0.29')"
ps="expr('2*int((@nf + 2)/2) * (@W / @nf + 0.29)')"
nrd="expr('0.29 / @W ')" nrs="expr('0.29 / @W ')"
sa=0 sb=0 sd=0
model=nfet_01v8_lvt
spiceprefix=X
}
C {sky130_fd_pr/nfet_01v8_lvt.sym} 660 -590 1 1 {name=M117
W=7
L=1
nf=1
mult=1
ad="expr('int((@nf + 1)/2) * @W / @nf * 0.29')"
pd="expr('2*int((@nf + 1)/2) * (@W / @nf + 0.29)')"
as="expr('int((@nf + 2)/2) * @W / @nf * 0.29')"
ps="expr('2*int((@nf + 2)/2) * (@W / @nf + 0.29)')"
nrd="expr('0.29 / @W ')" nrs="expr('0.29 / @W ')"
sa=0 sb=0 sd=0
model=nfet_01v8_lvt
spiceprefix=X
}
C {sky130_fd_pr/nfet_01v8_lvt.sym} 730 -590 3 0 {name=M118
W=7
L=1
nf=1
mult=1
ad="expr('int((@nf + 1)/2) * @W / @nf * 0.29')"
pd="expr('2*int((@nf + 1)/2) * (@W / @nf + 0.29)')"
as="expr('int((@nf + 2)/2) * @W / @nf * 0.29')"
ps="expr('2*int((@nf + 2)/2) * (@W / @nf + 0.29)')"
nrd="expr('0.29 / @W ')" nrs="expr('0.29 / @W ')"
sa=0 sb=0 sd=0
model=nfet_01v8_lvt
spiceprefix=X
}
C {sky130_fd_pr/nfet_01v8_lvt.sym} 800 -590 1 1 {name=M119
W=7
L=1
nf=1
mult=1
ad="expr('int((@nf + 1)/2) * @W / @nf * 0.29')"
pd="expr('2*int((@nf + 1)/2) * (@W / @nf + 0.29)')"
as="expr('int((@nf + 2)/2) * @W / @nf * 0.29')"
ps="expr('2*int((@nf + 2)/2) * (@W / @nf + 0.29)')"
nrd="expr('0.29 / @W ')" nrs="expr('0.29 / @W ')"
sa=0 sb=0 sd=0
model=nfet_01v8_lvt
spiceprefix=X
}
C {sky130_fd_pr/nfet_01v8_lvt.sym} 870 -590 3 0 {name=M120
W=7
L=1
nf=1
mult=1
ad="expr('int((@nf + 1)/2) * @W / @nf * 0.29')"
pd="expr('2*int((@nf + 1)/2) * (@W / @nf + 0.29)')"
as="expr('int((@nf + 2)/2) * @W / @nf * 0.29')"
ps="expr('2*int((@nf + 2)/2) * (@W / @nf + 0.29)')"
nrd="expr('0.29 / @W ')" nrs="expr('0.29 / @W ')"
sa=0 sb=0 sd=0
model=nfet_01v8_lvt
spiceprefix=X
}
C {sky130_fd_pr/nfet_01v8_lvt.sym} 940 -590 1 1 {name=M121
W=7
L=1
nf=1
mult=1
ad="expr('int((@nf + 1)/2) * @W / @nf * 0.29')"
pd="expr('2*int((@nf + 1)/2) * (@W / @nf + 0.29)')"
as="expr('int((@nf + 2)/2) * @W / @nf * 0.29')"
ps="expr('2*int((@nf + 2)/2) * (@W / @nf + 0.29)')"
nrd="expr('0.29 / @W ')" nrs="expr('0.29 / @W ')"
sa=0 sb=0 sd=0
model=nfet_01v8_lvt
spiceprefix=X
}
C {sky130_fd_pr/nfet_01v8_lvt.sym} 250 -810 3 1 {name=M122
W=7
L=1
nf=1
mult=1
ad="expr('int((@nf + 1)/2) * @W / @nf * 0.29')"
pd="expr('2*int((@nf + 1)/2) * (@W / @nf + 0.29)')"
as="expr('int((@nf + 2)/2) * @W / @nf * 0.29')"
ps="expr('2*int((@nf + 2)/2) * (@W / @nf + 0.29)')"
nrd="expr('0.29 / @W ')" nrs="expr('0.29 / @W ')"
sa=0 sb=0 sd=0
model=nfet_01v8_lvt
spiceprefix=X
}
C {sky130_fd_pr/nfet_01v8_lvt.sym} 1170 -810 1 0 {name=M123
W=7
L=1
nf=1
mult=1
ad="expr('int((@nf + 1)/2) * @W / @nf * 0.29')"
pd="expr('2*int((@nf + 1)/2) * (@W / @nf + 0.29)')"
as="expr('int((@nf + 2)/2) * @W / @nf * 0.29')"
ps="expr('2*int((@nf + 2)/2) * (@W / @nf + 0.29)')"
nrd="expr('0.29 / @W ')" nrs="expr('0.29 / @W ')"
sa=0 sb=0 sd=0
model=nfet_01v8_lvt
spiceprefix=X
}
C {sky130_fd_pr/nfet_01v8_lvt.sym} 1170 -590 1 1 {name=M124
W=7
L=1
nf=1
mult=1
ad="expr('int((@nf + 1)/2) * @W / @nf * 0.29')"
pd="expr('2*int((@nf + 1)/2) * (@W / @nf + 0.29)')"
as="expr('int((@nf + 2)/2) * @W / @nf * 0.29')"
ps="expr('2*int((@nf + 2)/2) * (@W / @nf + 0.29)')"
nrd="expr('0.29 / @W ')" nrs="expr('0.29 / @W ')"
sa=0 sb=0 sd=0
model=nfet_01v8_lvt
spiceprefix=X
}
C {sky130_fd_pr/nfet_01v8_lvt.sym} 240 -590 1 1 {name=M125
W=7
L=1
nf=1
mult=1
ad="expr('int((@nf + 1)/2) * @W / @nf * 0.29')"
pd="expr('2*int((@nf + 1)/2) * (@W / @nf + 0.29)')"
as="expr('int((@nf + 2)/2) * @W / @nf * 0.29')"
ps="expr('2*int((@nf + 2)/2) * (@W / @nf + 0.29)')"
nrd="expr('0.29 / @W ')" nrs="expr('0.29 / @W ')"
sa=0 sb=0 sd=0
model=nfet_01v8_lvt
spiceprefix=X
}
C {sky130_fd_pr/nfet_01v8_lvt.sym} 470 -1090 3 1 {name=M126
W=7
L=1
nf=1
mult=1
ad="expr('int((@nf + 1)/2) * @W / @nf * 0.29')"
pd="expr('2*int((@nf + 1)/2) * (@W / @nf + 0.29)')"
as="expr('int((@nf + 2)/2) * @W / @nf * 0.29')"
ps="expr('2*int((@nf + 2)/2) * (@W / @nf + 0.29)')"
nrd="expr('0.29 / @W ')" nrs="expr('0.29 / @W ')"
sa=0 sb=0 sd=0
model=nfet_01v8_lvt
spiceprefix=X
}
C {sky130_fd_pr/nfet_01v8_lvt.sym} 540 -1090 1 0 {name=M127
W=7
L=1
nf=1
mult=1
ad="expr('int((@nf + 1)/2) * @W / @nf * 0.29')"
pd="expr('2*int((@nf + 1)/2) * (@W / @nf + 0.29)')"
as="expr('int((@nf + 2)/2) * @W / @nf * 0.29')"
ps="expr('2*int((@nf + 2)/2) * (@W / @nf + 0.29)')"
nrd="expr('0.29 / @W ')" nrs="expr('0.29 / @W ')"
sa=0 sb=0 sd=0
model=nfet_01v8_lvt
spiceprefix=X
}
C {sky130_fd_pr/nfet_01v8_lvt.sym} 610 -1090 3 1 {name=M128
W=7
L=1
nf=1
mult=1
ad="expr('int((@nf + 1)/2) * @W / @nf * 0.29')"
pd="expr('2*int((@nf + 1)/2) * (@W / @nf + 0.29)')"
as="expr('int((@nf + 2)/2) * @W / @nf * 0.29')"
ps="expr('2*int((@nf + 2)/2) * (@W / @nf + 0.29)')"
nrd="expr('0.29 / @W ')" nrs="expr('0.29 / @W ')"
sa=0 sb=0 sd=0
model=nfet_01v8_lvt
spiceprefix=X
}
C {sky130_fd_pr/nfet_01v8_lvt.sym} 680 -1090 1 0 {name=M129
W=7
L=1
nf=1
mult=1
ad="expr('int((@nf + 1)/2) * @W / @nf * 0.29')"
pd="expr('2*int((@nf + 1)/2) * (@W / @nf + 0.29)')"
as="expr('int((@nf + 2)/2) * @W / @nf * 0.29')"
ps="expr('2*int((@nf + 2)/2) * (@W / @nf + 0.29)')"
nrd="expr('0.29 / @W ')" nrs="expr('0.29 / @W ')"
sa=0 sb=0 sd=0
model=nfet_01v8_lvt
spiceprefix=X
}
C {sky130_fd_pr/nfet_01v8_lvt.sym} 750 -1090 3 1 {name=M130
W=7
L=1
nf=1
mult=1
ad="expr('int((@nf + 1)/2) * @W / @nf * 0.29')"
pd="expr('2*int((@nf + 1)/2) * (@W / @nf + 0.29)')"
as="expr('int((@nf + 2)/2) * @W / @nf * 0.29')"
ps="expr('2*int((@nf + 2)/2) * (@W / @nf + 0.29)')"
nrd="expr('0.29 / @W ')" nrs="expr('0.29 / @W ')"
sa=0 sb=0 sd=0
model=nfet_01v8_lvt
spiceprefix=X
}
C {sky130_fd_pr/nfet_01v8_lvt.sym} 820 -1090 1 0 {name=M131
W=7
L=1
nf=1
mult=1
ad="expr('int((@nf + 1)/2) * @W / @nf * 0.29')"
pd="expr('2*int((@nf + 1)/2) * (@W / @nf + 0.29)')"
as="expr('int((@nf + 2)/2) * @W / @nf * 0.29')"
ps="expr('2*int((@nf + 2)/2) * (@W / @nf + 0.29)')"
nrd="expr('0.29 / @W ')" nrs="expr('0.29 / @W ')"
sa=0 sb=0 sd=0
model=nfet_01v8_lvt
spiceprefix=X
}
C {sky130_fd_pr/nfet_01v8_lvt.sym} 890 -1090 3 1 {name=M132
W=7
L=1
nf=1
mult=1
ad="expr('int((@nf + 1)/2) * @W / @nf * 0.29')"
pd="expr('2*int((@nf + 1)/2) * (@W / @nf + 0.29)')"
as="expr('int((@nf + 2)/2) * @W / @nf * 0.29')"
ps="expr('2*int((@nf + 2)/2) * (@W / @nf + 0.29)')"
nrd="expr('0.29 / @W ')" nrs="expr('0.29 / @W ')"
sa=0 sb=0 sd=0
model=nfet_01v8_lvt
spiceprefix=X
}
C {sky130_fd_pr/nfet_01v8_lvt.sym} 960 -1090 1 0 {name=M133
W=7
L=1
nf=1
mult=1
ad="expr('int((@nf + 1)/2) * @W / @nf * 0.29')"
pd="expr('2*int((@nf + 1)/2) * (@W / @nf + 0.29)')"
as="expr('int((@nf + 2)/2) * @W / @nf * 0.29')"
ps="expr('2*int((@nf + 2)/2) * (@W / @nf + 0.29)')"
nrd="expr('0.29 / @W ')" nrs="expr('0.29 / @W ')"
sa=0 sb=0 sd=0
model=nfet_01v8_lvt
spiceprefix=X
}
C {lab_wire.sym} 780 -1070 2 0 {name=p2 sig_type=std_logic lab=VSS}
C {sky130_fd_pr/nfet_01v8_lvt.sym} 410 -330 3 1 {name=M134
W=7
L=1
nf=1
mult=1
ad="expr('int((@nf + 1)/2) * @W / @nf * 0.29')"
pd="expr('2*int((@nf + 1)/2) * (@W / @nf + 0.29)')"
as="expr('int((@nf + 2)/2) * @W / @nf * 0.29')"
ps="expr('2*int((@nf + 2)/2) * (@W / @nf + 0.29)')"
nrd="expr('0.29 / @W ')" nrs="expr('0.29 / @W ')"
sa=0 sb=0 sd=0
model=nfet_01v8_lvt
spiceprefix=X
}
C {sky130_fd_pr/nfet_01v8_lvt.sym} 480 -330 1 0 {name=M135
W=7
L=1
nf=1
mult=1
ad="expr('int((@nf + 1)/2) * @W / @nf * 0.29')"
pd="expr('2*int((@nf + 1)/2) * (@W / @nf + 0.29)')"
as="expr('int((@nf + 2)/2) * @W / @nf * 0.29')"
ps="expr('2*int((@nf + 2)/2) * (@W / @nf + 0.29)')"
nrd="expr('0.29 / @W ')" nrs="expr('0.29 / @W ')"
sa=0 sb=0 sd=0
model=nfet_01v8_lvt
spiceprefix=X
}
C {sky130_fd_pr/nfet_01v8_lvt.sym} 550 -330 3 1 {name=M136
W=7
L=1
nf=1
mult=1
ad="expr('int((@nf + 1)/2) * @W / @nf * 0.29')"
pd="expr('2*int((@nf + 1)/2) * (@W / @nf + 0.29)')"
as="expr('int((@nf + 2)/2) * @W / @nf * 0.29')"
ps="expr('2*int((@nf + 2)/2) * (@W / @nf + 0.29)')"
nrd="expr('0.29 / @W ')" nrs="expr('0.29 / @W ')"
sa=0 sb=0 sd=0
model=nfet_01v8_lvt
spiceprefix=X
}
C {sky130_fd_pr/nfet_01v8_lvt.sym} 620 -330 1 0 {name=M137
W=7
L=1
nf=1
mult=1
ad="expr('int((@nf + 1)/2) * @W / @nf * 0.29')"
pd="expr('2*int((@nf + 1)/2) * (@W / @nf + 0.29)')"
as="expr('int((@nf + 2)/2) * @W / @nf * 0.29')"
ps="expr('2*int((@nf + 2)/2) * (@W / @nf + 0.29)')"
nrd="expr('0.29 / @W ')" nrs="expr('0.29 / @W ')"
sa=0 sb=0 sd=0
model=nfet_01v8_lvt
spiceprefix=X
}
C {sky130_fd_pr/nfet_01v8_lvt.sym} 690 -330 3 1 {name=M138
W=7
L=1
nf=1
mult=1
ad="expr('int((@nf + 1)/2) * @W / @nf * 0.29')"
pd="expr('2*int((@nf + 1)/2) * (@W / @nf + 0.29)')"
as="expr('int((@nf + 2)/2) * @W / @nf * 0.29')"
ps="expr('2*int((@nf + 2)/2) * (@W / @nf + 0.29)')"
nrd="expr('0.29 / @W ')" nrs="expr('0.29 / @W ')"
sa=0 sb=0 sd=0
model=nfet_01v8_lvt
spiceprefix=X
}
C {sky130_fd_pr/nfet_01v8_lvt.sym} 760 -330 1 0 {name=M139
W=7
L=1
nf=1
mult=1
ad="expr('int((@nf + 1)/2) * @W / @nf * 0.29')"
pd="expr('2*int((@nf + 1)/2) * (@W / @nf + 0.29)')"
as="expr('int((@nf + 2)/2) * @W / @nf * 0.29')"
ps="expr('2*int((@nf + 2)/2) * (@W / @nf + 0.29)')"
nrd="expr('0.29 / @W ')" nrs="expr('0.29 / @W ')"
sa=0 sb=0 sd=0
model=nfet_01v8_lvt
spiceprefix=X
}
C {sky130_fd_pr/nfet_01v8_lvt.sym} 830 -330 3 1 {name=M140
W=7
L=1
nf=1
mult=1
ad="expr('int((@nf + 1)/2) * @W / @nf * 0.29')"
pd="expr('2*int((@nf + 1)/2) * (@W / @nf + 0.29)')"
as="expr('int((@nf + 2)/2) * @W / @nf * 0.29')"
ps="expr('2*int((@nf + 2)/2) * (@W / @nf + 0.29)')"
nrd="expr('0.29 / @W ')" nrs="expr('0.29 / @W ')"
sa=0 sb=0 sd=0
model=nfet_01v8_lvt
spiceprefix=X
}
C {sky130_fd_pr/nfet_01v8_lvt.sym} 900 -330 1 0 {name=M141
W=7
L=1
nf=1
mult=1
ad="expr('int((@nf + 1)/2) * @W / @nf * 0.29')"
pd="expr('2*int((@nf + 1)/2) * (@W / @nf + 0.29)')"
as="expr('int((@nf + 2)/2) * @W / @nf * 0.29')"
ps="expr('2*int((@nf + 2)/2) * (@W / @nf + 0.29)')"
nrd="expr('0.29 / @W ')" nrs="expr('0.29 / @W ')"
sa=0 sb=0 sd=0
model=nfet_01v8_lvt
spiceprefix=X
}
C {lab_wire.sym} 720 -310 2 0 {name=p15 sig_type=std_logic lab=VSS}
C {sky130_fd_pr/nfet_01v8_lvt.sym} 380 -1090 3 1 {name=M142
W=7
L=1
nf=1
mult=1
ad="expr('int((@nf + 1)/2) * @W / @nf * 0.29')"
pd="expr('2*int((@nf + 1)/2) * (@W / @nf + 0.29)')"
as="expr('int((@nf + 2)/2) * @W / @nf * 0.29')"
ps="expr('2*int((@nf + 2)/2) * (@W / @nf + 0.29)')"
nrd="expr('0.29 / @W ')" nrs="expr('0.29 / @W ')"
sa=0 sb=0 sd=0
model=nfet_01v8_lvt
spiceprefix=X
}
C {sky130_fd_pr/nfet_01v8_lvt.sym} 1040 -1090 1 0 {name=M143
W=7
L=1
nf=1
mult=1
ad="expr('int((@nf + 1)/2) * @W / @nf * 0.29')"
pd="expr('2*int((@nf + 1)/2) * (@W / @nf + 0.29)')"
as="expr('int((@nf + 2)/2) * @W / @nf * 0.29')"
ps="expr('2*int((@nf + 2)/2) * (@W / @nf + 0.29)')"
nrd="expr('0.29 / @W ')" nrs="expr('0.29 / @W ')"
sa=0 sb=0 sd=0
model=nfet_01v8_lvt
spiceprefix=X
}
C {sky130_fd_pr/nfet_01v8_lvt.sym} 330 -330 3 1 {name=M144
W=7
L=1
nf=1
mult=1
ad="expr('int((@nf + 1)/2) * @W / @nf * 0.29')"
pd="expr('2*int((@nf + 1)/2) * (@W / @nf + 0.29)')"
as="expr('int((@nf + 2)/2) * @W / @nf * 0.29')"
ps="expr('2*int((@nf + 2)/2) * (@W / @nf + 0.29)')"
nrd="expr('0.29 / @W ')" nrs="expr('0.29 / @W ')"
sa=0 sb=0 sd=0
model=nfet_01v8_lvt
spiceprefix=X
}
C {sky130_fd_pr/nfet_01v8_lvt.sym} 990 -330 1 0 {name=M145
W=7
L=1
nf=1
mult=1
ad="expr('int((@nf + 1)/2) * @W / @nf * 0.29')"
pd="expr('2*int((@nf + 1)/2) * (@W / @nf + 0.29)')"
as="expr('int((@nf + 2)/2) * @W / @nf * 0.29')"
ps="expr('2*int((@nf + 2)/2) * (@W / @nf + 0.29)')"
nrd="expr('0.29 / @W ')" nrs="expr('0.29 / @W ')"
sa=0 sb=0 sd=0
model=nfet_01v8_lvt
spiceprefix=X
}
C {sky130_fd_pr/res_xhigh_po_1p41.sym} 670 -1330 0 0 {name=R1
L=14
model=res_xhigh_po_1p41
spiceprefix=X
mult=1}
